VERSION 5.7 ;
  NOWIREEXTENSIONATPIN ON ;
  DIVIDERCHAR "/" ;
  BUSBITCHARS "[]" ;
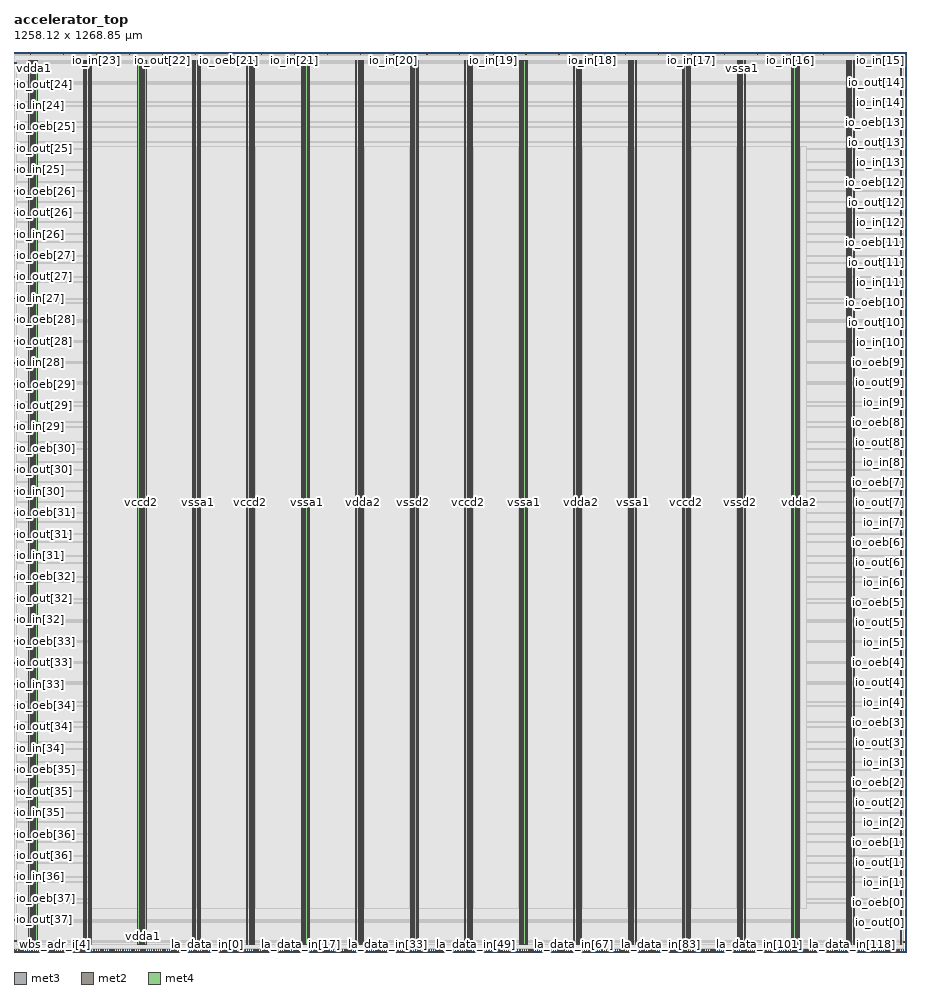
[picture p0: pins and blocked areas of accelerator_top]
MACRO accelerator_top
  CLASS BLOCK ;
  FOREIGN accelerator_top ;
  ORIGIN 0.000 0.000 ;
  SIZE 1258.125 BY 1268.845 ;
  PIN io_in[0]
    DIRECTION INPUT ;
    USE SIGNAL ;
    PORT
      LAYER met3 ;
        RECT 1254.125 13.640 1258.125 14.240 ;
    END
  END io_in[0]
  PIN io_in[10]
    DIRECTION INPUT ;
    USE SIGNAL ;
    PORT
      LAYER met3 ;
        RECT 1254.125 859.560 1258.125 860.160 ;
    END
  END io_in[10]
  PIN io_in[11]
    DIRECTION INPUT ;
    USE SIGNAL ;
    PORT
      LAYER met3 ;
        RECT 1254.125 943.880 1258.125 944.480 ;
    END
  END io_in[11]
  PIN io_in[12]
    DIRECTION INPUT ;
    USE SIGNAL ;
    PORT
      LAYER met3 ;
        RECT 1254.125 1028.200 1258.125 1028.800 ;
    END
  END io_in[12]
  PIN io_in[13]
    DIRECTION INPUT ;
    USE SIGNAL ;
    PORT
      LAYER met3 ;
        RECT 1254.125 1113.200 1258.125 1113.800 ;
    END
  END io_in[13]
  PIN io_in[14]
    DIRECTION INPUT ;
    USE SIGNAL ;
    PORT
      LAYER met3 ;
        RECT 1254.125 1197.520 1258.125 1198.120 ;
    END
  END io_in[14]
  PIN io_in[15]
    DIRECTION INPUT ;
    USE SIGNAL ;
    PORT
      LAYER met2 ;
        RECT 1234.270 1264.845 1234.550 1268.845 ;
    END
  END io_in[15]
  PIN io_in[16]
    DIRECTION INPUT ;
    USE SIGNAL ;
    PORT
      LAYER met2 ;
        RECT 1094.430 1264.845 1094.710 1268.845 ;
    END
  END io_in[16]
  PIN io_in[17]
    DIRECTION INPUT ;
    USE SIGNAL ;
    PORT
      LAYER met2 ;
        RECT 954.590 1264.845 954.870 1268.845 ;
    END
  END io_in[17]
  PIN io_in[18]
    DIRECTION INPUT ;
    USE SIGNAL ;
    PORT
      LAYER met2 ;
        RECT 815.210 1264.845 815.490 1268.845 ;
    END
  END io_in[18]
  PIN io_in[19]
    DIRECTION INPUT ;
    USE SIGNAL ;
    PORT
      LAYER met2 ;
        RECT 675.370 1264.845 675.650 1268.845 ;
    END
  END io_in[19]
  PIN io_in[1]
    DIRECTION INPUT ;
    USE SIGNAL ;
    PORT
      LAYER met3 ;
        RECT 1254.125 97.960 1258.125 98.560 ;
    END
  END io_in[1]
  PIN io_in[20]
    DIRECTION INPUT ;
    USE SIGNAL ;
    PORT
      LAYER met2 ;
        RECT 535.530 1264.845 535.810 1268.845 ;
    END
  END io_in[20]
  PIN io_in[21]
    DIRECTION INPUT ;
    USE SIGNAL ;
    PORT
      LAYER met2 ;
        RECT 395.690 1264.845 395.970 1268.845 ;
    END
  END io_in[21]
  PIN io_in[22]
    DIRECTION INPUT ;
    USE SIGNAL ;
    PORT
      LAYER met2 ;
        RECT 255.850 1264.845 256.130 1268.845 ;
    END
  END io_in[22]
  PIN io_in[23]
    DIRECTION INPUT ;
    USE SIGNAL ;
    PORT
      LAYER met2 ;
        RECT 116.010 1264.845 116.290 1268.845 ;
    END
  END io_in[23]
  PIN io_in[24]
    DIRECTION INPUT ;
    USE SIGNAL ;
    PORT
      LAYER met3 ;
        RECT 0.000 1192.760 4.000 1193.360 ;
    END
  END io_in[24]
  PIN io_in[25]
    DIRECTION INPUT ;
    USE SIGNAL ;
    PORT
      LAYER met3 ;
        RECT 0.000 1102.320 4.000 1102.920 ;
    END
  END io_in[25]
  PIN io_in[26]
    DIRECTION INPUT ;
    USE SIGNAL ;
    PORT
      LAYER met3 ;
        RECT 0.000 1011.880 4.000 1012.480 ;
    END
  END io_in[26]
  PIN io_in[27]
    DIRECTION INPUT ;
    USE SIGNAL ;
    PORT
      LAYER met3 ;
        RECT 0.000 920.760 4.000 921.360 ;
    END
  END io_in[27]
  PIN io_in[28]
    DIRECTION INPUT ;
    USE SIGNAL ;
    PORT
      LAYER met3 ;
        RECT 0.000 830.320 4.000 830.920 ;
    END
  END io_in[28]
  PIN io_in[29]
    DIRECTION INPUT ;
    USE SIGNAL ;
    PORT
      LAYER met3 ;
        RECT 0.000 739.880 4.000 740.480 ;
    END
  END io_in[29]
  PIN io_in[2]
    DIRECTION INPUT ;
    USE SIGNAL ;
    PORT
      LAYER met3 ;
        RECT 1254.125 182.280 1258.125 182.880 ;
    END
  END io_in[2]
  PIN io_in[30]
    DIRECTION INPUT ;
    USE SIGNAL ;
    PORT
      LAYER met3 ;
        RECT 0.000 649.440 4.000 650.040 ;
    END
  END io_in[30]
  PIN io_in[31]
    DIRECTION INPUT ;
    USE SIGNAL ;
    PORT
      LAYER met3 ;
        RECT 0.000 558.320 4.000 558.920 ;
    END
  END io_in[31]
  PIN io_in[32]
    DIRECTION INPUT ;
    USE SIGNAL ;
    PORT
      LAYER met3 ;
        RECT 0.000 467.880 4.000 468.480 ;
    END
  END io_in[32]
  PIN io_in[33]
    DIRECTION INPUT ;
    USE SIGNAL ;
    PORT
      LAYER met3 ;
        RECT 0.000 377.440 4.000 378.040 ;
    END
  END io_in[33]
  PIN io_in[34]
    DIRECTION INPUT ;
    USE SIGNAL ;
    PORT
      LAYER met3 ;
        RECT 0.000 286.320 4.000 286.920 ;
    END
  END io_in[34]
  PIN io_in[35]
    DIRECTION INPUT ;
    USE SIGNAL ;
    PORT
      LAYER met3 ;
        RECT 0.000 195.880 4.000 196.480 ;
    END
  END io_in[35]
  PIN io_in[36]
    DIRECTION INPUT ;
    USE SIGNAL ;
    PORT
      LAYER met3 ;
        RECT 0.000 105.440 4.000 106.040 ;
    END
  END io_in[36]
  PIN io_in[37]
    DIRECTION INPUT ;
    USE SIGNAL ;
    PORT
      LAYER met3 ;
        RECT 0.000 15.000 4.000 15.600 ;
    END
  END io_in[37]
  PIN io_in[3]
    DIRECTION INPUT ;
    USE SIGNAL ;
    PORT
      LAYER met3 ;
        RECT 1254.125 267.280 1258.125 267.880 ;
    END
  END io_in[3]
  PIN io_in[4]
    DIRECTION INPUT ;
    USE SIGNAL ;
    PORT
      LAYER met3 ;
        RECT 1254.125 351.600 1258.125 352.200 ;
    END
  END io_in[4]
  PIN io_in[5]
    DIRECTION INPUT ;
    USE SIGNAL ;
    PORT
      LAYER met3 ;
        RECT 1254.125 436.600 1258.125 437.200 ;
    END
  END io_in[5]
  PIN io_in[6]
    DIRECTION INPUT ;
    USE SIGNAL ;
    PORT
      LAYER met3 ;
        RECT 1254.125 520.920 1258.125 521.520 ;
    END
  END io_in[6]
  PIN io_in[7]
    DIRECTION INPUT ;
    USE SIGNAL ;
    PORT
      LAYER met3 ;
        RECT 1254.125 605.240 1258.125 605.840 ;
    END
  END io_in[7]
  PIN io_in[8]
    DIRECTION INPUT ;
    USE SIGNAL ;
    PORT
      LAYER met3 ;
        RECT 1254.125 690.240 1258.125 690.840 ;
    END
  END io_in[8]
  PIN io_in[9]
    DIRECTION INPUT ;
    USE SIGNAL ;
    PORT
      LAYER met3 ;
        RECT 1254.125 774.560 1258.125 775.160 ;
    END
  END io_in[9]
  PIN io_oeb[0]
    DIRECTION OUTPUT TRISTATE ;
    USE SIGNAL ;
    PORT
      LAYER met3 ;
        RECT 1254.125 69.400 1258.125 70.000 ;
    END
  END io_oeb[0]
  PIN io_oeb[10]
    DIRECTION OUTPUT TRISTATE ;
    USE SIGNAL ;
    PORT
      LAYER met3 ;
        RECT 1254.125 915.320 1258.125 915.920 ;
    END
  END io_oeb[10]
  PIN io_oeb[11]
    DIRECTION OUTPUT TRISTATE ;
    USE SIGNAL ;
    PORT
      LAYER met3 ;
        RECT 1254.125 1000.320 1258.125 1000.920 ;
    END
  END io_oeb[11]
  PIN io_oeb[12]
    DIRECTION OUTPUT TRISTATE ;
    USE SIGNAL ;
    PORT
      LAYER met3 ;
        RECT 1254.125 1084.640 1258.125 1085.240 ;
    END
  END io_oeb[12]
  PIN io_oeb[13]
    DIRECTION OUTPUT TRISTATE ;
    USE SIGNAL ;
    PORT
      LAYER met3 ;
        RECT 1254.125 1169.640 1258.125 1170.240 ;
    END
  END io_oeb[13]
  PIN io_oeb[14]
    DIRECTION OUTPUT TRISTATE ;
    USE SIGNAL ;
    PORT
      LAYER met3 ;
        RECT 1254.125 1253.960 1258.125 1254.560 ;
    END
  END io_oeb[14]
  PIN io_oeb[15]
    DIRECTION OUTPUT TRISTATE ;
    USE SIGNAL ;
    PORT
      LAYER met2 ;
        RECT 1141.350 1264.845 1141.630 1268.845 ;
    END
  END io_oeb[15]
  PIN io_oeb[16]
    DIRECTION OUTPUT TRISTATE ;
    USE SIGNAL ;
    PORT
      LAYER met2 ;
        RECT 1001.510 1264.845 1001.790 1268.845 ;
    END
  END io_oeb[16]
  PIN io_oeb[17]
    DIRECTION OUTPUT TRISTATE ;
    USE SIGNAL ;
    PORT
      LAYER met2 ;
        RECT 861.670 1264.845 861.950 1268.845 ;
    END
  END io_oeb[17]
  PIN io_oeb[18]
    DIRECTION OUTPUT TRISTATE ;
    USE SIGNAL ;
    PORT
      LAYER met2 ;
        RECT 721.830 1264.845 722.110 1268.845 ;
    END
  END io_oeb[18]
  PIN io_oeb[19]
    DIRECTION OUTPUT TRISTATE ;
    USE SIGNAL ;
    PORT
      LAYER met2 ;
        RECT 581.990 1264.845 582.270 1268.845 ;
    END
  END io_oeb[19]
  PIN io_oeb[1]
    DIRECTION OUTPUT TRISTATE ;
    USE SIGNAL ;
    PORT
      LAYER met3 ;
        RECT 1254.125 154.400 1258.125 155.000 ;
    END
  END io_oeb[1]
  PIN io_oeb[20]
    DIRECTION OUTPUT TRISTATE ;
    USE SIGNAL ;
    PORT
      LAYER met2 ;
        RECT 442.150 1264.845 442.430 1268.845 ;
    END
  END io_oeb[20]
  PIN io_oeb[21]
    DIRECTION OUTPUT TRISTATE ;
    USE SIGNAL ;
    PORT
      LAYER met2 ;
        RECT 302.310 1264.845 302.590 1268.845 ;
    END
  END io_oeb[21]
  PIN io_oeb[22]
    DIRECTION OUTPUT TRISTATE ;
    USE SIGNAL ;
    PORT
      LAYER met2 ;
        RECT 162.470 1264.845 162.750 1268.845 ;
    END
  END io_oeb[22]
  PIN io_oeb[23]
    DIRECTION OUTPUT TRISTATE ;
    USE SIGNAL ;
    PORT
      LAYER met2 ;
        RECT 23.090 1264.845 23.370 1268.845 ;
    END
  END io_oeb[23]
  PIN io_oeb[24]
    DIRECTION OUTPUT TRISTATE ;
    USE SIGNAL ;
    PORT
      LAYER met3 ;
        RECT 0.000 1253.280 4.000 1253.880 ;
    END
  END io_oeb[24]
  PIN io_oeb[25]
    DIRECTION OUTPUT TRISTATE ;
    USE SIGNAL ;
    PORT
      LAYER met3 ;
        RECT 0.000 1162.840 4.000 1163.440 ;
    END
  END io_oeb[25]
  PIN io_oeb[26]
    DIRECTION OUTPUT TRISTATE ;
    USE SIGNAL ;
    PORT
      LAYER met3 ;
        RECT 0.000 1072.400 4.000 1073.000 ;
    END
  END io_oeb[26]
  PIN io_oeb[27]
    DIRECTION OUTPUT TRISTATE ;
    USE SIGNAL ;
    PORT
      LAYER met3 ;
        RECT 0.000 981.280 4.000 981.880 ;
    END
  END io_oeb[27]
  PIN io_oeb[28]
    DIRECTION OUTPUT TRISTATE ;
    USE SIGNAL ;
    PORT
      LAYER met3 ;
        RECT 0.000 890.840 4.000 891.440 ;
    END
  END io_oeb[28]
  PIN io_oeb[29]
    DIRECTION OUTPUT TRISTATE ;
    USE SIGNAL ;
    PORT
      LAYER met3 ;
        RECT 0.000 800.400 4.000 801.000 ;
    END
  END io_oeb[29]
  PIN io_oeb[2]
    DIRECTION OUTPUT TRISTATE ;
    USE SIGNAL ;
    PORT
      LAYER met3 ;
        RECT 1254.125 238.720 1258.125 239.320 ;
    END
  END io_oeb[2]
  PIN io_oeb[30]
    DIRECTION OUTPUT TRISTATE ;
    USE SIGNAL ;
    PORT
      LAYER met3 ;
        RECT 0.000 709.280 4.000 709.880 ;
    END
  END io_oeb[30]
  PIN io_oeb[31]
    DIRECTION OUTPUT TRISTATE ;
    USE SIGNAL ;
    PORT
      LAYER met3 ;
        RECT 0.000 618.840 4.000 619.440 ;
    END
  END io_oeb[31]
  PIN io_oeb[32]
    DIRECTION OUTPUT TRISTATE ;
    USE SIGNAL ;
    PORT
      LAYER met3 ;
        RECT 0.000 528.400 4.000 529.000 ;
    END
  END io_oeb[32]
  PIN io_oeb[33]
    DIRECTION OUTPUT TRISTATE ;
    USE SIGNAL ;
    PORT
      LAYER met3 ;
        RECT 0.000 437.960 4.000 438.560 ;
    END
  END io_oeb[33]
  PIN io_oeb[34]
    DIRECTION OUTPUT TRISTATE ;
    USE SIGNAL ;
    PORT
      LAYER met3 ;
        RECT 0.000 346.840 4.000 347.440 ;
    END
  END io_oeb[34]
  PIN io_oeb[35]
    DIRECTION OUTPUT TRISTATE ;
    USE SIGNAL ;
    PORT
      LAYER met3 ;
        RECT 0.000 256.400 4.000 257.000 ;
    END
  END io_oeb[35]
  PIN io_oeb[36]
    DIRECTION OUTPUT TRISTATE ;
    USE SIGNAL ;
    PORT
      LAYER met3 ;
        RECT 0.000 165.960 4.000 166.560 ;
    END
  END io_oeb[36]
  PIN io_oeb[37]
    DIRECTION OUTPUT TRISTATE ;
    USE SIGNAL ;
    PORT
      LAYER met3 ;
        RECT 0.000 74.840 4.000 75.440 ;
    END
  END io_oeb[37]
  PIN io_oeb[3]
    DIRECTION OUTPUT TRISTATE ;
    USE SIGNAL ;
    PORT
      LAYER met3 ;
        RECT 1254.125 323.720 1258.125 324.320 ;
    END
  END io_oeb[3]
  PIN io_oeb[4]
    DIRECTION OUTPUT TRISTATE ;
    USE SIGNAL ;
    PORT
      LAYER met3 ;
        RECT 1254.125 408.040 1258.125 408.640 ;
    END
  END io_oeb[4]
  PIN io_oeb[5]
    DIRECTION OUTPUT TRISTATE ;
    USE SIGNAL ;
    PORT
      LAYER met3 ;
        RECT 1254.125 492.360 1258.125 492.960 ;
    END
  END io_oeb[5]
  PIN io_oeb[6]
    DIRECTION OUTPUT TRISTATE ;
    USE SIGNAL ;
    PORT
      LAYER met3 ;
        RECT 1254.125 577.360 1258.125 577.960 ;
    END
  END io_oeb[6]
  PIN io_oeb[7]
    DIRECTION OUTPUT TRISTATE ;
    USE SIGNAL ;
    PORT
      LAYER met3 ;
        RECT 1254.125 661.680 1258.125 662.280 ;
    END
  END io_oeb[7]
  PIN io_oeb[8]
    DIRECTION OUTPUT TRISTATE ;
    USE SIGNAL ;
    PORT
      LAYER met3 ;
        RECT 1254.125 746.680 1258.125 747.280 ;
    END
  END io_oeb[8]
  PIN io_oeb[9]
    DIRECTION OUTPUT TRISTATE ;
    USE SIGNAL ;
    PORT
      LAYER met3 ;
        RECT 1254.125 831.000 1258.125 831.600 ;
    END
  END io_oeb[9]
  PIN io_out[0]
    DIRECTION OUTPUT TRISTATE ;
    USE SIGNAL ;
    PORT
      LAYER met3 ;
        RECT 1254.125 41.520 1258.125 42.120 ;
    END
  END io_out[0]
  PIN io_out[10]
    DIRECTION OUTPUT TRISTATE ;
    USE SIGNAL ;
    PORT
      LAYER met3 ;
        RECT 1254.125 887.440 1258.125 888.040 ;
    END
  END io_out[10]
  PIN io_out[11]
    DIRECTION OUTPUT TRISTATE ;
    USE SIGNAL ;
    PORT
      LAYER met3 ;
        RECT 1254.125 971.760 1258.125 972.360 ;
    END
  END io_out[11]
  PIN io_out[12]
    DIRECTION OUTPUT TRISTATE ;
    USE SIGNAL ;
    PORT
      LAYER met3 ;
        RECT 1254.125 1056.760 1258.125 1057.360 ;
    END
  END io_out[12]
  PIN io_out[13]
    DIRECTION OUTPUT TRISTATE ;
    USE SIGNAL ;
    PORT
      LAYER met3 ;
        RECT 1254.125 1141.080 1258.125 1141.680 ;
    END
  END io_out[13]
  PIN io_out[14]
    DIRECTION OUTPUT TRISTATE ;
    USE SIGNAL ;
    PORT
      LAYER met3 ;
        RECT 1254.125 1226.080 1258.125 1226.680 ;
    END
  END io_out[14]
  PIN io_out[15]
    DIRECTION OUTPUT TRISTATE ;
    USE SIGNAL ;
    PORT
      LAYER met2 ;
        RECT 1187.810 1264.845 1188.090 1268.845 ;
    END
  END io_out[15]
  PIN io_out[16]
    DIRECTION OUTPUT TRISTATE ;
    USE SIGNAL ;
    PORT
      LAYER met2 ;
        RECT 1047.970 1264.845 1048.250 1268.845 ;
    END
  END io_out[16]
  PIN io_out[17]
    DIRECTION OUTPUT TRISTATE ;
    USE SIGNAL ;
    PORT
      LAYER met2 ;
        RECT 908.130 1264.845 908.410 1268.845 ;
    END
  END io_out[17]
  PIN io_out[18]
    DIRECTION OUTPUT TRISTATE ;
    USE SIGNAL ;
    PORT
      LAYER met2 ;
        RECT 768.290 1264.845 768.570 1268.845 ;
    END
  END io_out[18]
  PIN io_out[19]
    DIRECTION OUTPUT TRISTATE ;
    USE SIGNAL ;
    PORT
      LAYER met2 ;
        RECT 628.450 1264.845 628.730 1268.845 ;
    END
  END io_out[19]
  PIN io_out[1]
    DIRECTION OUTPUT TRISTATE ;
    USE SIGNAL ;
    PORT
      LAYER met3 ;
        RECT 1254.125 125.840 1258.125 126.440 ;
    END
  END io_out[1]
  PIN io_out[20]
    DIRECTION OUTPUT TRISTATE ;
    USE SIGNAL ;
    PORT
      LAYER met2 ;
        RECT 488.610 1264.845 488.890 1268.845 ;
    END
  END io_out[20]
  PIN io_out[21]
    DIRECTION OUTPUT TRISTATE ;
    USE SIGNAL ;
    PORT
      LAYER met2 ;
        RECT 349.230 1264.845 349.510 1268.845 ;
    END
  END io_out[21]
  PIN io_out[22]
    DIRECTION OUTPUT TRISTATE ;
    USE SIGNAL ;
    PORT
      LAYER met2 ;
        RECT 209.390 1264.845 209.670 1268.845 ;
    END
  END io_out[22]
  PIN io_out[23]
    DIRECTION OUTPUT TRISTATE ;
    USE SIGNAL ;
    PORT
      LAYER met2 ;
        RECT 69.550 1264.845 69.830 1268.845 ;
    END
  END io_out[23]
  PIN io_out[24]
    DIRECTION OUTPUT TRISTATE ;
    USE SIGNAL ;
    PORT
      LAYER met3 ;
        RECT 0.000 1223.360 4.000 1223.960 ;
    END
  END io_out[24]
  PIN io_out[25]
    DIRECTION OUTPUT TRISTATE ;
    USE SIGNAL ;
    PORT
      LAYER met3 ;
        RECT 0.000 1132.240 4.000 1132.840 ;
    END
  END io_out[25]
  PIN io_out[26]
    DIRECTION OUTPUT TRISTATE ;
    USE SIGNAL ;
    PORT
      LAYER met3 ;
        RECT 0.000 1041.800 4.000 1042.400 ;
    END
  END io_out[26]
  PIN io_out[27]
    DIRECTION OUTPUT TRISTATE ;
    USE SIGNAL ;
    PORT
      LAYER met3 ;
        RECT 0.000 951.360 4.000 951.960 ;
    END
  END io_out[27]
  PIN io_out[28]
    DIRECTION OUTPUT TRISTATE ;
    USE SIGNAL ;
    PORT
      LAYER met3 ;
        RECT 0.000 860.920 4.000 861.520 ;
    END
  END io_out[28]
  PIN io_out[29]
    DIRECTION OUTPUT TRISTATE ;
    USE SIGNAL ;
    PORT
      LAYER met3 ;
        RECT 0.000 769.800 4.000 770.400 ;
    END
  END io_out[29]
  PIN io_out[2]
    DIRECTION OUTPUT TRISTATE ;
    USE SIGNAL ;
    PORT
      LAYER met3 ;
        RECT 1254.125 210.840 1258.125 211.440 ;
    END
  END io_out[2]
  PIN io_out[30]
    DIRECTION OUTPUT TRISTATE ;
    USE SIGNAL ;
    PORT
      LAYER met3 ;
        RECT 0.000 679.360 4.000 679.960 ;
    END
  END io_out[30]
  PIN io_out[31]
    DIRECTION OUTPUT TRISTATE ;
    USE SIGNAL ;
    PORT
      LAYER met3 ;
        RECT 0.000 588.920 4.000 589.520 ;
    END
  END io_out[31]
  PIN io_out[32]
    DIRECTION OUTPUT TRISTATE ;
    USE SIGNAL ;
    PORT
      LAYER met3 ;
        RECT 0.000 497.800 4.000 498.400 ;
    END
  END io_out[32]
  PIN io_out[33]
    DIRECTION OUTPUT TRISTATE ;
    USE SIGNAL ;
    PORT
      LAYER met3 ;
        RECT 0.000 407.360 4.000 407.960 ;
    END
  END io_out[33]
  PIN io_out[34]
    DIRECTION OUTPUT TRISTATE ;
    USE SIGNAL ;
    PORT
      LAYER met3 ;
        RECT 0.000 316.920 4.000 317.520 ;
    END
  END io_out[34]
  PIN io_out[35]
    DIRECTION OUTPUT TRISTATE ;
    USE SIGNAL ;
    PORT
      LAYER met3 ;
        RECT 0.000 226.480 4.000 227.080 ;
    END
  END io_out[35]
  PIN io_out[36]
    DIRECTION OUTPUT TRISTATE ;
    USE SIGNAL ;
    PORT
      LAYER met3 ;
        RECT 0.000 135.360 4.000 135.960 ;
    END
  END io_out[36]
  PIN io_out[37]
    DIRECTION OUTPUT TRISTATE ;
    USE SIGNAL ;
    PORT
      LAYER met3 ;
        RECT 0.000 44.920 4.000 45.520 ;
    END
  END io_out[37]
  PIN io_out[3]
    DIRECTION OUTPUT TRISTATE ;
    USE SIGNAL ;
    PORT
      LAYER met3 ;
        RECT 1254.125 295.160 1258.125 295.760 ;
    END
  END io_out[3]
  PIN io_out[4]
    DIRECTION OUTPUT TRISTATE ;
    USE SIGNAL ;
    PORT
      LAYER met3 ;
        RECT 1254.125 380.160 1258.125 380.760 ;
    END
  END io_out[4]
  PIN io_out[5]
    DIRECTION OUTPUT TRISTATE ;
    USE SIGNAL ;
    PORT
      LAYER met3 ;
        RECT 1254.125 464.480 1258.125 465.080 ;
    END
  END io_out[5]
  PIN io_out[6]
    DIRECTION OUTPUT TRISTATE ;
    USE SIGNAL ;
    PORT
      LAYER met3 ;
        RECT 1254.125 548.800 1258.125 549.400 ;
    END
  END io_out[6]
  PIN io_out[7]
    DIRECTION OUTPUT TRISTATE ;
    USE SIGNAL ;
    PORT
      LAYER met3 ;
        RECT 1254.125 633.800 1258.125 634.400 ;
    END
  END io_out[7]
  PIN io_out[8]
    DIRECTION OUTPUT TRISTATE ;
    USE SIGNAL ;
    PORT
      LAYER met3 ;
        RECT 1254.125 718.120 1258.125 718.720 ;
    END
  END io_out[8]
  PIN io_out[9]
    DIRECTION OUTPUT TRISTATE ;
    USE SIGNAL ;
    PORT
      LAYER met3 ;
        RECT 1254.125 803.120 1258.125 803.720 ;
    END
  END io_out[9]
  PIN la_data_in[0]
    DIRECTION INPUT ;
    USE SIGNAL ;
    PORT
      LAYER met2 ;
        RECT 272.870 0.000 273.150 4.000 ;
    END
  END la_data_in[0]
  PIN la_data_in[100]
    DIRECTION INPUT ;
    USE SIGNAL ;
    PORT
      LAYER met2 ;
        RECT 1043.370 0.000 1043.650 4.000 ;
    END
  END la_data_in[100]
  PIN la_data_in[101]
    DIRECTION INPUT ;
    USE SIGNAL ;
    PORT
      LAYER met2 ;
        RECT 1050.730 0.000 1051.010 4.000 ;
    END
  END la_data_in[101]
  PIN la_data_in[102]
    DIRECTION INPUT ;
    USE SIGNAL ;
    PORT
      LAYER met2 ;
        RECT 1058.550 0.000 1058.830 4.000 ;
    END
  END la_data_in[102]
  PIN la_data_in[103]
    DIRECTION INPUT ;
    USE SIGNAL ;
    PORT
      LAYER met2 ;
        RECT 1066.370 0.000 1066.650 4.000 ;
    END
  END la_data_in[103]
  PIN la_data_in[104]
    DIRECTION INPUT ;
    USE SIGNAL ;
    PORT
      LAYER met2 ;
        RECT 1074.190 0.000 1074.470 4.000 ;
    END
  END la_data_in[104]
  PIN la_data_in[105]
    DIRECTION INPUT ;
    USE SIGNAL ;
    PORT
      LAYER met2 ;
        RECT 1081.550 0.000 1081.830 4.000 ;
    END
  END la_data_in[105]
  PIN la_data_in[106]
    DIRECTION INPUT ;
    USE SIGNAL ;
    PORT
      LAYER met2 ;
        RECT 1089.370 0.000 1089.650 4.000 ;
    END
  END la_data_in[106]
  PIN la_data_in[107]
    DIRECTION INPUT ;
    USE SIGNAL ;
    PORT
      LAYER met2 ;
        RECT 1097.190 0.000 1097.470 4.000 ;
    END
  END la_data_in[107]
  PIN la_data_in[108]
    DIRECTION INPUT ;
    USE SIGNAL ;
    PORT
      LAYER met2 ;
        RECT 1105.010 0.000 1105.290 4.000 ;
    END
  END la_data_in[108]
  PIN la_data_in[109]
    DIRECTION INPUT ;
    USE SIGNAL ;
    PORT
      LAYER met2 ;
        RECT 1112.370 0.000 1112.650 4.000 ;
    END
  END la_data_in[109]
  PIN la_data_in[10]
    DIRECTION INPUT ;
    USE SIGNAL ;
    PORT
      LAYER met2 ;
        RECT 350.150 0.000 350.430 4.000 ;
    END
  END la_data_in[10]
  PIN la_data_in[110]
    DIRECTION INPUT ;
    USE SIGNAL ;
    PORT
      LAYER met2 ;
        RECT 1120.190 0.000 1120.470 4.000 ;
    END
  END la_data_in[110]
  PIN la_data_in[111]
    DIRECTION INPUT ;
    USE SIGNAL ;
    PORT
      LAYER met2 ;
        RECT 1128.010 0.000 1128.290 4.000 ;
    END
  END la_data_in[111]
  PIN la_data_in[112]
    DIRECTION INPUT ;
    USE SIGNAL ;
    PORT
      LAYER met2 ;
        RECT 1135.830 0.000 1136.110 4.000 ;
    END
  END la_data_in[112]
  PIN la_data_in[113]
    DIRECTION INPUT ;
    USE SIGNAL ;
    PORT
      LAYER met2 ;
        RECT 1143.190 0.000 1143.470 4.000 ;
    END
  END la_data_in[113]
  PIN la_data_in[114]
    DIRECTION INPUT ;
    USE SIGNAL ;
    PORT
      LAYER met2 ;
        RECT 1151.010 0.000 1151.290 4.000 ;
    END
  END la_data_in[114]
  PIN la_data_in[115]
    DIRECTION INPUT ;
    USE SIGNAL ;
    PORT
      LAYER met2 ;
        RECT 1158.830 0.000 1159.110 4.000 ;
    END
  END la_data_in[115]
  PIN la_data_in[116]
    DIRECTION INPUT ;
    USE SIGNAL ;
    PORT
      LAYER met2 ;
        RECT 1166.650 0.000 1166.930 4.000 ;
    END
  END la_data_in[116]
  PIN la_data_in[117]
    DIRECTION INPUT ;
    USE SIGNAL ;
    PORT
      LAYER met2 ;
        RECT 1174.010 0.000 1174.290 4.000 ;
    END
  END la_data_in[117]
  PIN la_data_in[118]
    DIRECTION INPUT ;
    USE SIGNAL ;
    PORT
      LAYER met2 ;
        RECT 1181.830 0.000 1182.110 4.000 ;
    END
  END la_data_in[118]
  PIN la_data_in[119]
    DIRECTION INPUT ;
    USE SIGNAL ;
    PORT
      LAYER met2 ;
        RECT 1189.650 0.000 1189.930 4.000 ;
    END
  END la_data_in[119]
  PIN la_data_in[11]
    DIRECTION INPUT ;
    USE SIGNAL ;
    PORT
      LAYER met2 ;
        RECT 357.510 0.000 357.790 4.000 ;
    END
  END la_data_in[11]
  PIN la_data_in[120]
    DIRECTION INPUT ;
    USE SIGNAL ;
    PORT
      LAYER met2 ;
        RECT 1197.470 0.000 1197.750 4.000 ;
    END
  END la_data_in[120]
  PIN la_data_in[121]
    DIRECTION INPUT ;
    USE SIGNAL ;
    PORT
      LAYER met2 ;
        RECT 1204.830 0.000 1205.110 4.000 ;
    END
  END la_data_in[121]
  PIN la_data_in[122]
    DIRECTION INPUT ;
    USE SIGNAL ;
    PORT
      LAYER met2 ;
        RECT 1212.650 0.000 1212.930 4.000 ;
    END
  END la_data_in[122]
  PIN la_data_in[123]
    DIRECTION INPUT ;
    USE SIGNAL ;
    PORT
      LAYER met2 ;
        RECT 1220.470 0.000 1220.750 4.000 ;
    END
  END la_data_in[123]
  PIN la_data_in[124]
    DIRECTION INPUT ;
    USE SIGNAL ;
    PORT
      LAYER met2 ;
        RECT 1228.290 0.000 1228.570 4.000 ;
    END
  END la_data_in[124]
  PIN la_data_in[125]
    DIRECTION INPUT ;
    USE SIGNAL ;
    PORT
      LAYER met2 ;
        RECT 1235.650 0.000 1235.930 4.000 ;
    END
  END la_data_in[125]
  PIN la_data_in[126]
    DIRECTION INPUT ;
    USE SIGNAL ;
    PORT
      LAYER met2 ;
        RECT 1243.470 0.000 1243.750 4.000 ;
    END
  END la_data_in[126]
  PIN la_data_in[127]
    DIRECTION INPUT ;
    USE SIGNAL ;
    PORT
      LAYER met2 ;
        RECT 1251.290 0.000 1251.570 4.000 ;
    END
  END la_data_in[127]
  PIN la_data_in[12]
    DIRECTION INPUT ;
    USE SIGNAL ;
    PORT
      LAYER met2 ;
        RECT 365.330 0.000 365.610 4.000 ;
    END
  END la_data_in[12]
  PIN la_data_in[13]
    DIRECTION INPUT ;
    USE SIGNAL ;
    PORT
      LAYER met2 ;
        RECT 373.150 0.000 373.430 4.000 ;
    END
  END la_data_in[13]
  PIN la_data_in[14]
    DIRECTION INPUT ;
    USE SIGNAL ;
    PORT
      LAYER met2 ;
        RECT 380.970 0.000 381.250 4.000 ;
    END
  END la_data_in[14]
  PIN la_data_in[15]
    DIRECTION INPUT ;
    USE SIGNAL ;
    PORT
      LAYER met2 ;
        RECT 388.330 0.000 388.610 4.000 ;
    END
  END la_data_in[15]
  PIN la_data_in[16]
    DIRECTION INPUT ;
    USE SIGNAL ;
    PORT
      LAYER met2 ;
        RECT 396.150 0.000 396.430 4.000 ;
    END
  END la_data_in[16]
  PIN la_data_in[17]
    DIRECTION INPUT ;
    USE SIGNAL ;
    PORT
      LAYER met2 ;
        RECT 403.970 0.000 404.250 4.000 ;
    END
  END la_data_in[17]
  PIN la_data_in[18]
    DIRECTION INPUT ;
    USE SIGNAL ;
    PORT
      LAYER met2 ;
        RECT 411.790 0.000 412.070 4.000 ;
    END
  END la_data_in[18]
  PIN la_data_in[19]
    DIRECTION INPUT ;
    USE SIGNAL ;
    PORT
      LAYER met2 ;
        RECT 419.150 0.000 419.430 4.000 ;
    END
  END la_data_in[19]
  PIN la_data_in[1]
    DIRECTION INPUT ;
    USE SIGNAL ;
    PORT
      LAYER met2 ;
        RECT 280.690 0.000 280.970 4.000 ;
    END
  END la_data_in[1]
  PIN la_data_in[20]
    DIRECTION INPUT ;
    USE SIGNAL ;
    PORT
      LAYER met2 ;
        RECT 426.970 0.000 427.250 4.000 ;
    END
  END la_data_in[20]
  PIN la_data_in[21]
    DIRECTION INPUT ;
    USE SIGNAL ;
    PORT
      LAYER met2 ;
        RECT 434.790 0.000 435.070 4.000 ;
    END
  END la_data_in[21]
  PIN la_data_in[22]
    DIRECTION INPUT ;
    USE SIGNAL ;
    PORT
      LAYER met2 ;
        RECT 442.610 0.000 442.890 4.000 ;
    END
  END la_data_in[22]
  PIN la_data_in[23]
    DIRECTION INPUT ;
    USE SIGNAL ;
    PORT
      LAYER met2 ;
        RECT 449.970 0.000 450.250 4.000 ;
    END
  END la_data_in[23]
  PIN la_data_in[24]
    DIRECTION INPUT ;
    USE SIGNAL ;
    PORT
      LAYER met2 ;
        RECT 457.790 0.000 458.070 4.000 ;
    END
  END la_data_in[24]
  PIN la_data_in[25]
    DIRECTION INPUT ;
    USE SIGNAL ;
    PORT
      LAYER met2 ;
        RECT 465.610 0.000 465.890 4.000 ;
    END
  END la_data_in[25]
  PIN la_data_in[26]
    DIRECTION INPUT ;
    USE SIGNAL ;
    PORT
      LAYER met2 ;
        RECT 473.430 0.000 473.710 4.000 ;
    END
  END la_data_in[26]
  PIN la_data_in[27]
    DIRECTION INPUT ;
    USE SIGNAL ;
    PORT
      LAYER met2 ;
        RECT 480.790 0.000 481.070 4.000 ;
    END
  END la_data_in[27]
  PIN la_data_in[28]
    DIRECTION INPUT ;
    USE SIGNAL ;
    PORT
      LAYER met2 ;
        RECT 488.610 0.000 488.890 4.000 ;
    END
  END la_data_in[28]
  PIN la_data_in[29]
    DIRECTION INPUT ;
    USE SIGNAL ;
    PORT
      LAYER met2 ;
        RECT 496.430 0.000 496.710 4.000 ;
    END
  END la_data_in[29]
  PIN la_data_in[2]
    DIRECTION INPUT ;
    USE SIGNAL ;
    PORT
      LAYER met2 ;
        RECT 288.510 0.000 288.790 4.000 ;
    END
  END la_data_in[2]
  PIN la_data_in[30]
    DIRECTION INPUT ;
    USE SIGNAL ;
    PORT
      LAYER met2 ;
        RECT 504.250 0.000 504.530 4.000 ;
    END
  END la_data_in[30]
  PIN la_data_in[31]
    DIRECTION INPUT ;
    USE SIGNAL ;
    PORT
      LAYER met2 ;
        RECT 511.610 0.000 511.890 4.000 ;
    END
  END la_data_in[31]
  PIN la_data_in[32]
    DIRECTION INPUT ;
    USE SIGNAL ;
    PORT
      LAYER met2 ;
        RECT 519.430 0.000 519.710 4.000 ;
    END
  END la_data_in[32]
  PIN la_data_in[33]
    DIRECTION INPUT ;
    USE SIGNAL ;
    PORT
      LAYER met2 ;
        RECT 527.250 0.000 527.530 4.000 ;
    END
  END la_data_in[33]
  PIN la_data_in[34]
    DIRECTION INPUT ;
    USE SIGNAL ;
    PORT
      LAYER met2 ;
        RECT 534.610 0.000 534.890 4.000 ;
    END
  END la_data_in[34]
  PIN la_data_in[35]
    DIRECTION INPUT ;
    USE SIGNAL ;
    PORT
      LAYER met2 ;
        RECT 542.430 0.000 542.710 4.000 ;
    END
  END la_data_in[35]
  PIN la_data_in[36]
    DIRECTION INPUT ;
    USE SIGNAL ;
    PORT
      LAYER met2 ;
        RECT 550.250 0.000 550.530 4.000 ;
    END
  END la_data_in[36]
  PIN la_data_in[37]
    DIRECTION INPUT ;
    USE SIGNAL ;
    PORT
      LAYER met2 ;
        RECT 558.070 0.000 558.350 4.000 ;
    END
  END la_data_in[37]
  PIN la_data_in[38]
    DIRECTION INPUT ;
    USE SIGNAL ;
    PORT
      LAYER met2 ;
        RECT 565.430 0.000 565.710 4.000 ;
    END
  END la_data_in[38]
  PIN la_data_in[39]
    DIRECTION INPUT ;
    USE SIGNAL ;
    PORT
      LAYER met2 ;
        RECT 573.250 0.000 573.530 4.000 ;
    END
  END la_data_in[39]
  PIN la_data_in[3]
    DIRECTION INPUT ;
    USE SIGNAL ;
    PORT
      LAYER met2 ;
        RECT 295.870 0.000 296.150 4.000 ;
    END
  END la_data_in[3]
  PIN la_data_in[40]
    DIRECTION INPUT ;
    USE SIGNAL ;
    PORT
      LAYER met2 ;
        RECT 581.070 0.000 581.350 4.000 ;
    END
  END la_data_in[40]
  PIN la_data_in[41]
    DIRECTION INPUT ;
    USE SIGNAL ;
    PORT
      LAYER met2 ;
        RECT 588.890 0.000 589.170 4.000 ;
    END
  END la_data_in[41]
  PIN la_data_in[42]
    DIRECTION INPUT ;
    USE SIGNAL ;
    PORT
      LAYER met2 ;
        RECT 596.250 0.000 596.530 4.000 ;
    END
  END la_data_in[42]
  PIN la_data_in[43]
    DIRECTION INPUT ;
    USE SIGNAL ;
    PORT
      LAYER met2 ;
        RECT 604.070 0.000 604.350 4.000 ;
    END
  END la_data_in[43]
  PIN la_data_in[44]
    DIRECTION INPUT ;
    USE SIGNAL ;
    PORT
      LAYER met2 ;
        RECT 611.890 0.000 612.170 4.000 ;
    END
  END la_data_in[44]
  PIN la_data_in[45]
    DIRECTION INPUT ;
    USE SIGNAL ;
    PORT
      LAYER met2 ;
        RECT 619.710 0.000 619.990 4.000 ;
    END
  END la_data_in[45]
  PIN la_data_in[46]
    DIRECTION INPUT ;
    USE SIGNAL ;
    PORT
      LAYER met2 ;
        RECT 627.070 0.000 627.350 4.000 ;
    END
  END la_data_in[46]
  PIN la_data_in[47]
    DIRECTION INPUT ;
    USE SIGNAL ;
    PORT
      LAYER met2 ;
        RECT 634.890 0.000 635.170 4.000 ;
    END
  END la_data_in[47]
  PIN la_data_in[48]
    DIRECTION INPUT ;
    USE SIGNAL ;
    PORT
      LAYER met2 ;
        RECT 642.710 0.000 642.990 4.000 ;
    END
  END la_data_in[48]
  PIN la_data_in[49]
    DIRECTION INPUT ;
    USE SIGNAL ;
    PORT
      LAYER met2 ;
        RECT 650.530 0.000 650.810 4.000 ;
    END
  END la_data_in[49]
  PIN la_data_in[4]
    DIRECTION INPUT ;
    USE SIGNAL ;
    PORT
      LAYER met2 ;
        RECT 303.690 0.000 303.970 4.000 ;
    END
  END la_data_in[4]
  PIN la_data_in[50]
    DIRECTION INPUT ;
    USE SIGNAL ;
    PORT
      LAYER met2 ;
        RECT 657.890 0.000 658.170 4.000 ;
    END
  END la_data_in[50]
  PIN la_data_in[51]
    DIRECTION INPUT ;
    USE SIGNAL ;
    PORT
      LAYER met2 ;
        RECT 665.710 0.000 665.990 4.000 ;
    END
  END la_data_in[51]
  PIN la_data_in[52]
    DIRECTION INPUT ;
    USE SIGNAL ;
    PORT
      LAYER met2 ;
        RECT 673.530 0.000 673.810 4.000 ;
    END
  END la_data_in[52]
  PIN la_data_in[53]
    DIRECTION INPUT ;
    USE SIGNAL ;
    PORT
      LAYER met2 ;
        RECT 681.350 0.000 681.630 4.000 ;
    END
  END la_data_in[53]
  PIN la_data_in[54]
    DIRECTION INPUT ;
    USE SIGNAL ;
    PORT
      LAYER met2 ;
        RECT 688.710 0.000 688.990 4.000 ;
    END
  END la_data_in[54]
  PIN la_data_in[55]
    DIRECTION INPUT ;
    USE SIGNAL ;
    PORT
      LAYER met2 ;
        RECT 696.530 0.000 696.810 4.000 ;
    END
  END la_data_in[55]
  PIN la_data_in[56]
    DIRECTION INPUT ;
    USE SIGNAL ;
    PORT
      LAYER met2 ;
        RECT 704.350 0.000 704.630 4.000 ;
    END
  END la_data_in[56]
  PIN la_data_in[57]
    DIRECTION INPUT ;
    USE SIGNAL ;
    PORT
      LAYER met2 ;
        RECT 712.170 0.000 712.450 4.000 ;
    END
  END la_data_in[57]
  PIN la_data_in[58]
    DIRECTION INPUT ;
    USE SIGNAL ;
    PORT
      LAYER met2 ;
        RECT 719.530 0.000 719.810 4.000 ;
    END
  END la_data_in[58]
  PIN la_data_in[59]
    DIRECTION INPUT ;
    USE SIGNAL ;
    PORT
      LAYER met2 ;
        RECT 727.350 0.000 727.630 4.000 ;
    END
  END la_data_in[59]
  PIN la_data_in[5]
    DIRECTION INPUT ;
    USE SIGNAL ;
    PORT
      LAYER met2 ;
        RECT 311.510 0.000 311.790 4.000 ;
    END
  END la_data_in[5]
  PIN la_data_in[60]
    DIRECTION INPUT ;
    USE SIGNAL ;
    PORT
      LAYER met2 ;
        RECT 735.170 0.000 735.450 4.000 ;
    END
  END la_data_in[60]
  PIN la_data_in[61]
    DIRECTION INPUT ;
    USE SIGNAL ;
    PORT
      LAYER met2 ;
        RECT 742.990 0.000 743.270 4.000 ;
    END
  END la_data_in[61]
  PIN la_data_in[62]
    DIRECTION INPUT ;
    USE SIGNAL ;
    PORT
      LAYER met2 ;
        RECT 750.350 0.000 750.630 4.000 ;
    END
  END la_data_in[62]
  PIN la_data_in[63]
    DIRECTION INPUT ;
    USE SIGNAL ;
    PORT
      LAYER met2 ;
        RECT 758.170 0.000 758.450 4.000 ;
    END
  END la_data_in[63]
  PIN la_data_in[64]
    DIRECTION INPUT ;
    USE SIGNAL ;
    PORT
      LAYER met2 ;
        RECT 765.990 0.000 766.270 4.000 ;
    END
  END la_data_in[64]
  PIN la_data_in[65]
    DIRECTION INPUT ;
    USE SIGNAL ;
    PORT
      LAYER met2 ;
        RECT 773.810 0.000 774.090 4.000 ;
    END
  END la_data_in[65]
  PIN la_data_in[66]
    DIRECTION INPUT ;
    USE SIGNAL ;
    PORT
      LAYER met2 ;
        RECT 781.170 0.000 781.450 4.000 ;
    END
  END la_data_in[66]
  PIN la_data_in[67]
    DIRECTION INPUT ;
    USE SIGNAL ;
    PORT
      LAYER met2 ;
        RECT 788.990 0.000 789.270 4.000 ;
    END
  END la_data_in[67]
  PIN la_data_in[68]
    DIRECTION INPUT ;
    USE SIGNAL ;
    PORT
      LAYER met2 ;
        RECT 796.810 0.000 797.090 4.000 ;
    END
  END la_data_in[68]
  PIN la_data_in[69]
    DIRECTION INPUT ;
    USE SIGNAL ;
    PORT
      LAYER met2 ;
        RECT 804.630 0.000 804.910 4.000 ;
    END
  END la_data_in[69]
  PIN la_data_in[6]
    DIRECTION INPUT ;
    USE SIGNAL ;
    PORT
      LAYER met2 ;
        RECT 319.330 0.000 319.610 4.000 ;
    END
  END la_data_in[6]
  PIN la_data_in[70]
    DIRECTION INPUT ;
    USE SIGNAL ;
    PORT
      LAYER met2 ;
        RECT 811.990 0.000 812.270 4.000 ;
    END
  END la_data_in[70]
  PIN la_data_in[71]
    DIRECTION INPUT ;
    USE SIGNAL ;
    PORT
      LAYER met2 ;
        RECT 819.810 0.000 820.090 4.000 ;
    END
  END la_data_in[71]
  PIN la_data_in[72]
    DIRECTION INPUT ;
    USE SIGNAL ;
    PORT
      LAYER met2 ;
        RECT 827.630 0.000 827.910 4.000 ;
    END
  END la_data_in[72]
  PIN la_data_in[73]
    DIRECTION INPUT ;
    USE SIGNAL ;
    PORT
      LAYER met2 ;
        RECT 835.450 0.000 835.730 4.000 ;
    END
  END la_data_in[73]
  PIN la_data_in[74]
    DIRECTION INPUT ;
    USE SIGNAL ;
    PORT
      LAYER met2 ;
        RECT 842.810 0.000 843.090 4.000 ;
    END
  END la_data_in[74]
  PIN la_data_in[75]
    DIRECTION INPUT ;
    USE SIGNAL ;
    PORT
      LAYER met2 ;
        RECT 850.630 0.000 850.910 4.000 ;
    END
  END la_data_in[75]
  PIN la_data_in[76]
    DIRECTION INPUT ;
    USE SIGNAL ;
    PORT
      LAYER met2 ;
        RECT 858.450 0.000 858.730 4.000 ;
    END
  END la_data_in[76]
  PIN la_data_in[77]
    DIRECTION INPUT ;
    USE SIGNAL ;
    PORT
      LAYER met2 ;
        RECT 866.270 0.000 866.550 4.000 ;
    END
  END la_data_in[77]
  PIN la_data_in[78]
    DIRECTION INPUT ;
    USE SIGNAL ;
    PORT
      LAYER met2 ;
        RECT 873.630 0.000 873.910 4.000 ;
    END
  END la_data_in[78]
  PIN la_data_in[79]
    DIRECTION INPUT ;
    USE SIGNAL ;
    PORT
      LAYER met2 ;
        RECT 881.450 0.000 881.730 4.000 ;
    END
  END la_data_in[79]
  PIN la_data_in[7]
    DIRECTION INPUT ;
    USE SIGNAL ;
    PORT
      LAYER met2 ;
        RECT 326.690 0.000 326.970 4.000 ;
    END
  END la_data_in[7]
  PIN la_data_in[80]
    DIRECTION INPUT ;
    USE SIGNAL ;
    PORT
      LAYER met2 ;
        RECT 889.270 0.000 889.550 4.000 ;
    END
  END la_data_in[80]
  PIN la_data_in[81]
    DIRECTION INPUT ;
    USE SIGNAL ;
    PORT
      LAYER met2 ;
        RECT 896.630 0.000 896.910 4.000 ;
    END
  END la_data_in[81]
  PIN la_data_in[82]
    DIRECTION INPUT ;
    USE SIGNAL ;
    PORT
      LAYER met2 ;
        RECT 904.450 0.000 904.730 4.000 ;
    END
  END la_data_in[82]
  PIN la_data_in[83]
    DIRECTION INPUT ;
    USE SIGNAL ;
    PORT
      LAYER met2 ;
        RECT 912.270 0.000 912.550 4.000 ;
    END
  END la_data_in[83]
  PIN la_data_in[84]
    DIRECTION INPUT ;
    USE SIGNAL ;
    PORT
      LAYER met2 ;
        RECT 920.090 0.000 920.370 4.000 ;
    END
  END la_data_in[84]
  PIN la_data_in[85]
    DIRECTION INPUT ;
    USE SIGNAL ;
    PORT
      LAYER met2 ;
        RECT 927.450 0.000 927.730 4.000 ;
    END
  END la_data_in[85]
  PIN la_data_in[86]
    DIRECTION INPUT ;
    USE SIGNAL ;
    PORT
      LAYER met2 ;
        RECT 935.270 0.000 935.550 4.000 ;
    END
  END la_data_in[86]
  PIN la_data_in[87]
    DIRECTION INPUT ;
    USE SIGNAL ;
    PORT
      LAYER met2 ;
        RECT 943.090 0.000 943.370 4.000 ;
    END
  END la_data_in[87]
  PIN la_data_in[88]
    DIRECTION INPUT ;
    USE SIGNAL ;
    PORT
      LAYER met2 ;
        RECT 950.910 0.000 951.190 4.000 ;
    END
  END la_data_in[88]
  PIN la_data_in[89]
    DIRECTION INPUT ;
    USE SIGNAL ;
    PORT
      LAYER met2 ;
        RECT 958.270 0.000 958.550 4.000 ;
    END
  END la_data_in[89]
  PIN la_data_in[8]
    DIRECTION INPUT ;
    USE SIGNAL ;
    PORT
      LAYER met2 ;
        RECT 334.510 0.000 334.790 4.000 ;
    END
  END la_data_in[8]
  PIN la_data_in[90]
    DIRECTION INPUT ;
    USE SIGNAL ;
    PORT
      LAYER met2 ;
        RECT 966.090 0.000 966.370 4.000 ;
    END
  END la_data_in[90]
  PIN la_data_in[91]
    DIRECTION INPUT ;
    USE SIGNAL ;
    PORT
      LAYER met2 ;
        RECT 973.910 0.000 974.190 4.000 ;
    END
  END la_data_in[91]
  PIN la_data_in[92]
    DIRECTION INPUT ;
    USE SIGNAL ;
    PORT
      LAYER met2 ;
        RECT 981.730 0.000 982.010 4.000 ;
    END
  END la_data_in[92]
  PIN la_data_in[93]
    DIRECTION INPUT ;
    USE SIGNAL ;
    PORT
      LAYER met2 ;
        RECT 989.090 0.000 989.370 4.000 ;
    END
  END la_data_in[93]
  PIN la_data_in[94]
    DIRECTION INPUT ;
    USE SIGNAL ;
    PORT
      LAYER met2 ;
        RECT 996.910 0.000 997.190 4.000 ;
    END
  END la_data_in[94]
  PIN la_data_in[95]
    DIRECTION INPUT ;
    USE SIGNAL ;
    PORT
      LAYER met2 ;
        RECT 1004.730 0.000 1005.010 4.000 ;
    END
  END la_data_in[95]
  PIN la_data_in[96]
    DIRECTION INPUT ;
    USE SIGNAL ;
    PORT
      LAYER met2 ;
        RECT 1012.550 0.000 1012.830 4.000 ;
    END
  END la_data_in[96]
  PIN la_data_in[97]
    DIRECTION INPUT ;
    USE SIGNAL ;
    PORT
      LAYER met2 ;
        RECT 1019.910 0.000 1020.190 4.000 ;
    END
  END la_data_in[97]
  PIN la_data_in[98]
    DIRECTION INPUT ;
    USE SIGNAL ;
    PORT
      LAYER met2 ;
        RECT 1027.730 0.000 1028.010 4.000 ;
    END
  END la_data_in[98]
  PIN la_data_in[99]
    DIRECTION INPUT ;
    USE SIGNAL ;
    PORT
      LAYER met2 ;
        RECT 1035.550 0.000 1035.830 4.000 ;
    END
  END la_data_in[99]
  PIN la_data_in[9]
    DIRECTION INPUT ;
    USE SIGNAL ;
    PORT
      LAYER met2 ;
        RECT 342.330 0.000 342.610 4.000 ;
    END
  END la_data_in[9]
  PIN la_data_out[0]
    DIRECTION OUTPUT TRISTATE ;
    USE SIGNAL ;
    PORT
      LAYER met2 ;
        RECT 275.630 0.000 275.910 4.000 ;
    END
  END la_data_out[0]
  PIN la_data_out[100]
    DIRECTION OUTPUT TRISTATE ;
    USE SIGNAL ;
    PORT
      LAYER met2 ;
        RECT 1045.670 0.000 1045.950 4.000 ;
    END
  END la_data_out[100]
  PIN la_data_out[101]
    DIRECTION OUTPUT TRISTATE ;
    USE SIGNAL ;
    PORT
      LAYER met2 ;
        RECT 1053.490 0.000 1053.770 4.000 ;
    END
  END la_data_out[101]
  PIN la_data_out[102]
    DIRECTION OUTPUT TRISTATE ;
    USE SIGNAL ;
    PORT
      LAYER met2 ;
        RECT 1061.310 0.000 1061.590 4.000 ;
    END
  END la_data_out[102]
  PIN la_data_out[103]
    DIRECTION OUTPUT TRISTATE ;
    USE SIGNAL ;
    PORT
      LAYER met2 ;
        RECT 1068.670 0.000 1068.950 4.000 ;
    END
  END la_data_out[103]
  PIN la_data_out[104]
    DIRECTION OUTPUT TRISTATE ;
    USE SIGNAL ;
    PORT
      LAYER met2 ;
        RECT 1076.490 0.000 1076.770 4.000 ;
    END
  END la_data_out[104]
  PIN la_data_out[105]
    DIRECTION OUTPUT TRISTATE ;
    USE SIGNAL ;
    PORT
      LAYER met2 ;
        RECT 1084.310 0.000 1084.590 4.000 ;
    END
  END la_data_out[105]
  PIN la_data_out[106]
    DIRECTION OUTPUT TRISTATE ;
    USE SIGNAL ;
    PORT
      LAYER met2 ;
        RECT 1092.130 0.000 1092.410 4.000 ;
    END
  END la_data_out[106]
  PIN la_data_out[107]
    DIRECTION OUTPUT TRISTATE ;
    USE SIGNAL ;
    PORT
      LAYER met2 ;
        RECT 1099.490 0.000 1099.770 4.000 ;
    END
  END la_data_out[107]
  PIN la_data_out[108]
    DIRECTION OUTPUT TRISTATE ;
    USE SIGNAL ;
    PORT
      LAYER met2 ;
        RECT 1107.310 0.000 1107.590 4.000 ;
    END
  END la_data_out[108]
  PIN la_data_out[109]
    DIRECTION OUTPUT TRISTATE ;
    USE SIGNAL ;
    PORT
      LAYER met2 ;
        RECT 1115.130 0.000 1115.410 4.000 ;
    END
  END la_data_out[109]
  PIN la_data_out[10]
    DIRECTION OUTPUT TRISTATE ;
    USE SIGNAL ;
    PORT
      LAYER met2 ;
        RECT 352.450 0.000 352.730 4.000 ;
    END
  END la_data_out[10]
  PIN la_data_out[110]
    DIRECTION OUTPUT TRISTATE ;
    USE SIGNAL ;
    PORT
      LAYER met2 ;
        RECT 1122.950 0.000 1123.230 4.000 ;
    END
  END la_data_out[110]
  PIN la_data_out[111]
    DIRECTION OUTPUT TRISTATE ;
    USE SIGNAL ;
    PORT
      LAYER met2 ;
        RECT 1130.310 0.000 1130.590 4.000 ;
    END
  END la_data_out[111]
  PIN la_data_out[112]
    DIRECTION OUTPUT TRISTATE ;
    USE SIGNAL ;
    PORT
      LAYER met2 ;
        RECT 1138.130 0.000 1138.410 4.000 ;
    END
  END la_data_out[112]
  PIN la_data_out[113]
    DIRECTION OUTPUT TRISTATE ;
    USE SIGNAL ;
    PORT
      LAYER met2 ;
        RECT 1145.950 0.000 1146.230 4.000 ;
    END
  END la_data_out[113]
  PIN la_data_out[114]
    DIRECTION OUTPUT TRISTATE ;
    USE SIGNAL ;
    PORT
      LAYER met2 ;
        RECT 1153.770 0.000 1154.050 4.000 ;
    END
  END la_data_out[114]
  PIN la_data_out[115]
    DIRECTION OUTPUT TRISTATE ;
    USE SIGNAL ;
    PORT
      LAYER met2 ;
        RECT 1161.130 0.000 1161.410 4.000 ;
    END
  END la_data_out[115]
  PIN la_data_out[116]
    DIRECTION OUTPUT TRISTATE ;
    USE SIGNAL ;
    PORT
      LAYER met2 ;
        RECT 1168.950 0.000 1169.230 4.000 ;
    END
  END la_data_out[116]
  PIN la_data_out[117]
    DIRECTION OUTPUT TRISTATE ;
    USE SIGNAL ;
    PORT
      LAYER met2 ;
        RECT 1176.770 0.000 1177.050 4.000 ;
    END
  END la_data_out[117]
  PIN la_data_out[118]
    DIRECTION OUTPUT TRISTATE ;
    USE SIGNAL ;
    PORT
      LAYER met2 ;
        RECT 1184.590 0.000 1184.870 4.000 ;
    END
  END la_data_out[118]
  PIN la_data_out[119]
    DIRECTION OUTPUT TRISTATE ;
    USE SIGNAL ;
    PORT
      LAYER met2 ;
        RECT 1191.950 0.000 1192.230 4.000 ;
    END
  END la_data_out[119]
  PIN la_data_out[11]
    DIRECTION OUTPUT TRISTATE ;
    USE SIGNAL ;
    PORT
      LAYER met2 ;
        RECT 360.270 0.000 360.550 4.000 ;
    END
  END la_data_out[11]
  PIN la_data_out[120]
    DIRECTION OUTPUT TRISTATE ;
    USE SIGNAL ;
    PORT
      LAYER met2 ;
        RECT 1199.770 0.000 1200.050 4.000 ;
    END
  END la_data_out[120]
  PIN la_data_out[121]
    DIRECTION OUTPUT TRISTATE ;
    USE SIGNAL ;
    PORT
      LAYER met2 ;
        RECT 1207.590 0.000 1207.870 4.000 ;
    END
  END la_data_out[121]
  PIN la_data_out[122]
    DIRECTION OUTPUT TRISTATE ;
    USE SIGNAL ;
    PORT
      LAYER met2 ;
        RECT 1215.410 0.000 1215.690 4.000 ;
    END
  END la_data_out[122]
  PIN la_data_out[123]
    DIRECTION OUTPUT TRISTATE ;
    USE SIGNAL ;
    PORT
      LAYER met2 ;
        RECT 1222.770 0.000 1223.050 4.000 ;
    END
  END la_data_out[123]
  PIN la_data_out[124]
    DIRECTION OUTPUT TRISTATE ;
    USE SIGNAL ;
    PORT
      LAYER met2 ;
        RECT 1230.590 0.000 1230.870 4.000 ;
    END
  END la_data_out[124]
  PIN la_data_out[125]
    DIRECTION OUTPUT TRISTATE ;
    USE SIGNAL ;
    PORT
      LAYER met2 ;
        RECT 1238.410 0.000 1238.690 4.000 ;
    END
  END la_data_out[125]
  PIN la_data_out[126]
    DIRECTION OUTPUT TRISTATE ;
    USE SIGNAL ;
    PORT
      LAYER met2 ;
        RECT 1246.230 0.000 1246.510 4.000 ;
    END
  END la_data_out[126]
  PIN la_data_out[127]
    DIRECTION OUTPUT TRISTATE ;
    USE SIGNAL ;
    PORT
      LAYER met2 ;
        RECT 1253.590 0.000 1253.870 4.000 ;
    END
  END la_data_out[127]
  PIN la_data_out[12]
    DIRECTION OUTPUT TRISTATE ;
    USE SIGNAL ;
    PORT
      LAYER met2 ;
        RECT 368.090 0.000 368.370 4.000 ;
    END
  END la_data_out[12]
  PIN la_data_out[13]
    DIRECTION OUTPUT TRISTATE ;
    USE SIGNAL ;
    PORT
      LAYER met2 ;
        RECT 375.450 0.000 375.730 4.000 ;
    END
  END la_data_out[13]
  PIN la_data_out[14]
    DIRECTION OUTPUT TRISTATE ;
    USE SIGNAL ;
    PORT
      LAYER met2 ;
        RECT 383.270 0.000 383.550 4.000 ;
    END
  END la_data_out[14]
  PIN la_data_out[15]
    DIRECTION OUTPUT TRISTATE ;
    USE SIGNAL ;
    PORT
      LAYER met2 ;
        RECT 391.090 0.000 391.370 4.000 ;
    END
  END la_data_out[15]
  PIN la_data_out[16]
    DIRECTION OUTPUT TRISTATE ;
    USE SIGNAL ;
    PORT
      LAYER met2 ;
        RECT 398.910 0.000 399.190 4.000 ;
    END
  END la_data_out[16]
  PIN la_data_out[17]
    DIRECTION OUTPUT TRISTATE ;
    USE SIGNAL ;
    PORT
      LAYER met2 ;
        RECT 406.270 0.000 406.550 4.000 ;
    END
  END la_data_out[17]
  PIN la_data_out[18]
    DIRECTION OUTPUT TRISTATE ;
    USE SIGNAL ;
    PORT
      LAYER met2 ;
        RECT 414.090 0.000 414.370 4.000 ;
    END
  END la_data_out[18]
  PIN la_data_out[19]
    DIRECTION OUTPUT TRISTATE ;
    USE SIGNAL ;
    PORT
      LAYER met2 ;
        RECT 421.910 0.000 422.190 4.000 ;
    END
  END la_data_out[19]
  PIN la_data_out[1]
    DIRECTION OUTPUT TRISTATE ;
    USE SIGNAL ;
    PORT
      LAYER met2 ;
        RECT 282.990 0.000 283.270 4.000 ;
    END
  END la_data_out[1]
  PIN la_data_out[20]
    DIRECTION OUTPUT TRISTATE ;
    USE SIGNAL ;
    PORT
      LAYER met2 ;
        RECT 429.730 0.000 430.010 4.000 ;
    END
  END la_data_out[20]
  PIN la_data_out[21]
    DIRECTION OUTPUT TRISTATE ;
    USE SIGNAL ;
    PORT
      LAYER met2 ;
        RECT 437.090 0.000 437.370 4.000 ;
    END
  END la_data_out[21]
  PIN la_data_out[22]
    DIRECTION OUTPUT TRISTATE ;
    USE SIGNAL ;
    PORT
      LAYER met2 ;
        RECT 444.910 0.000 445.190 4.000 ;
    END
  END la_data_out[22]
  PIN la_data_out[23]
    DIRECTION OUTPUT TRISTATE ;
    USE SIGNAL ;
    PORT
      LAYER met2 ;
        RECT 452.730 0.000 453.010 4.000 ;
    END
  END la_data_out[23]
  PIN la_data_out[24]
    DIRECTION OUTPUT TRISTATE ;
    USE SIGNAL ;
    PORT
      LAYER met2 ;
        RECT 460.550 0.000 460.830 4.000 ;
    END
  END la_data_out[24]
  PIN la_data_out[25]
    DIRECTION OUTPUT TRISTATE ;
    USE SIGNAL ;
    PORT
      LAYER met2 ;
        RECT 467.910 0.000 468.190 4.000 ;
    END
  END la_data_out[25]
  PIN la_data_out[26]
    DIRECTION OUTPUT TRISTATE ;
    USE SIGNAL ;
    PORT
      LAYER met2 ;
        RECT 475.730 0.000 476.010 4.000 ;
    END
  END la_data_out[26]
  PIN la_data_out[27]
    DIRECTION OUTPUT TRISTATE ;
    USE SIGNAL ;
    PORT
      LAYER met2 ;
        RECT 483.550 0.000 483.830 4.000 ;
    END
  END la_data_out[27]
  PIN la_data_out[28]
    DIRECTION OUTPUT TRISTATE ;
    USE SIGNAL ;
    PORT
      LAYER met2 ;
        RECT 491.370 0.000 491.650 4.000 ;
    END
  END la_data_out[28]
  PIN la_data_out[29]
    DIRECTION OUTPUT TRISTATE ;
    USE SIGNAL ;
    PORT
      LAYER met2 ;
        RECT 498.730 0.000 499.010 4.000 ;
    END
  END la_data_out[29]
  PIN la_data_out[2]
    DIRECTION OUTPUT TRISTATE ;
    USE SIGNAL ;
    PORT
      LAYER met2 ;
        RECT 290.810 0.000 291.090 4.000 ;
    END
  END la_data_out[2]
  PIN la_data_out[30]
    DIRECTION OUTPUT TRISTATE ;
    USE SIGNAL ;
    PORT
      LAYER met2 ;
        RECT 506.550 0.000 506.830 4.000 ;
    END
  END la_data_out[30]
  PIN la_data_out[31]
    DIRECTION OUTPUT TRISTATE ;
    USE SIGNAL ;
    PORT
      LAYER met2 ;
        RECT 514.370 0.000 514.650 4.000 ;
    END
  END la_data_out[31]
  PIN la_data_out[32]
    DIRECTION OUTPUT TRISTATE ;
    USE SIGNAL ;
    PORT
      LAYER met2 ;
        RECT 522.190 0.000 522.470 4.000 ;
    END
  END la_data_out[32]
  PIN la_data_out[33]
    DIRECTION OUTPUT TRISTATE ;
    USE SIGNAL ;
    PORT
      LAYER met2 ;
        RECT 529.550 0.000 529.830 4.000 ;
    END
  END la_data_out[33]
  PIN la_data_out[34]
    DIRECTION OUTPUT TRISTATE ;
    USE SIGNAL ;
    PORT
      LAYER met2 ;
        RECT 537.370 0.000 537.650 4.000 ;
    END
  END la_data_out[34]
  PIN la_data_out[35]
    DIRECTION OUTPUT TRISTATE ;
    USE SIGNAL ;
    PORT
      LAYER met2 ;
        RECT 545.190 0.000 545.470 4.000 ;
    END
  END la_data_out[35]
  PIN la_data_out[36]
    DIRECTION OUTPUT TRISTATE ;
    USE SIGNAL ;
    PORT
      LAYER met2 ;
        RECT 553.010 0.000 553.290 4.000 ;
    END
  END la_data_out[36]
  PIN la_data_out[37]
    DIRECTION OUTPUT TRISTATE ;
    USE SIGNAL ;
    PORT
      LAYER met2 ;
        RECT 560.370 0.000 560.650 4.000 ;
    END
  END la_data_out[37]
  PIN la_data_out[38]
    DIRECTION OUTPUT TRISTATE ;
    USE SIGNAL ;
    PORT
      LAYER met2 ;
        RECT 568.190 0.000 568.470 4.000 ;
    END
  END la_data_out[38]
  PIN la_data_out[39]
    DIRECTION OUTPUT TRISTATE ;
    USE SIGNAL ;
    PORT
      LAYER met2 ;
        RECT 576.010 0.000 576.290 4.000 ;
    END
  END la_data_out[39]
  PIN la_data_out[3]
    DIRECTION OUTPUT TRISTATE ;
    USE SIGNAL ;
    PORT
      LAYER met2 ;
        RECT 298.630 0.000 298.910 4.000 ;
    END
  END la_data_out[3]
  PIN la_data_out[40]
    DIRECTION OUTPUT TRISTATE ;
    USE SIGNAL ;
    PORT
      LAYER met2 ;
        RECT 583.830 0.000 584.110 4.000 ;
    END
  END la_data_out[40]
  PIN la_data_out[41]
    DIRECTION OUTPUT TRISTATE ;
    USE SIGNAL ;
    PORT
      LAYER met2 ;
        RECT 591.190 0.000 591.470 4.000 ;
    END
  END la_data_out[41]
  PIN la_data_out[42]
    DIRECTION OUTPUT TRISTATE ;
    USE SIGNAL ;
    PORT
      LAYER met2 ;
        RECT 599.010 0.000 599.290 4.000 ;
    END
  END la_data_out[42]
  PIN la_data_out[43]
    DIRECTION OUTPUT TRISTATE ;
    USE SIGNAL ;
    PORT
      LAYER met2 ;
        RECT 606.830 0.000 607.110 4.000 ;
    END
  END la_data_out[43]
  PIN la_data_out[44]
    DIRECTION OUTPUT TRISTATE ;
    USE SIGNAL ;
    PORT
      LAYER met2 ;
        RECT 614.650 0.000 614.930 4.000 ;
    END
  END la_data_out[44]
  PIN la_data_out[45]
    DIRECTION OUTPUT TRISTATE ;
    USE SIGNAL ;
    PORT
      LAYER met2 ;
        RECT 622.010 0.000 622.290 4.000 ;
    END
  END la_data_out[45]
  PIN la_data_out[46]
    DIRECTION OUTPUT TRISTATE ;
    USE SIGNAL ;
    PORT
      LAYER met2 ;
        RECT 629.830 0.000 630.110 4.000 ;
    END
  END la_data_out[46]
  PIN la_data_out[47]
    DIRECTION OUTPUT TRISTATE ;
    USE SIGNAL ;
    PORT
      LAYER met2 ;
        RECT 637.650 0.000 637.930 4.000 ;
    END
  END la_data_out[47]
  PIN la_data_out[48]
    DIRECTION OUTPUT TRISTATE ;
    USE SIGNAL ;
    PORT
      LAYER met2 ;
        RECT 645.010 0.000 645.290 4.000 ;
    END
  END la_data_out[48]
  PIN la_data_out[49]
    DIRECTION OUTPUT TRISTATE ;
    USE SIGNAL ;
    PORT
      LAYER met2 ;
        RECT 652.830 0.000 653.110 4.000 ;
    END
  END la_data_out[49]
  PIN la_data_out[4]
    DIRECTION OUTPUT TRISTATE ;
    USE SIGNAL ;
    PORT
      LAYER met2 ;
        RECT 306.450 0.000 306.730 4.000 ;
    END
  END la_data_out[4]
  PIN la_data_out[50]
    DIRECTION OUTPUT TRISTATE ;
    USE SIGNAL ;
    PORT
      LAYER met2 ;
        RECT 660.650 0.000 660.930 4.000 ;
    END
  END la_data_out[50]
  PIN la_data_out[51]
    DIRECTION OUTPUT TRISTATE ;
    USE SIGNAL ;
    PORT
      LAYER met2 ;
        RECT 668.470 0.000 668.750 4.000 ;
    END
  END la_data_out[51]
  PIN la_data_out[52]
    DIRECTION OUTPUT TRISTATE ;
    USE SIGNAL ;
    PORT
      LAYER met2 ;
        RECT 675.830 0.000 676.110 4.000 ;
    END
  END la_data_out[52]
  PIN la_data_out[53]
    DIRECTION OUTPUT TRISTATE ;
    USE SIGNAL ;
    PORT
      LAYER met2 ;
        RECT 683.650 0.000 683.930 4.000 ;
    END
  END la_data_out[53]
  PIN la_data_out[54]
    DIRECTION OUTPUT TRISTATE ;
    USE SIGNAL ;
    PORT
      LAYER met2 ;
        RECT 691.470 0.000 691.750 4.000 ;
    END
  END la_data_out[54]
  PIN la_data_out[55]
    DIRECTION OUTPUT TRISTATE ;
    USE SIGNAL ;
    PORT
      LAYER met2 ;
        RECT 699.290 0.000 699.570 4.000 ;
    END
  END la_data_out[55]
  PIN la_data_out[56]
    DIRECTION OUTPUT TRISTATE ;
    USE SIGNAL ;
    PORT
      LAYER met2 ;
        RECT 706.650 0.000 706.930 4.000 ;
    END
  END la_data_out[56]
  PIN la_data_out[57]
    DIRECTION OUTPUT TRISTATE ;
    USE SIGNAL ;
    PORT
      LAYER met2 ;
        RECT 714.470 0.000 714.750 4.000 ;
    END
  END la_data_out[57]
  PIN la_data_out[58]
    DIRECTION OUTPUT TRISTATE ;
    USE SIGNAL ;
    PORT
      LAYER met2 ;
        RECT 722.290 0.000 722.570 4.000 ;
    END
  END la_data_out[58]
  PIN la_data_out[59]
    DIRECTION OUTPUT TRISTATE ;
    USE SIGNAL ;
    PORT
      LAYER met2 ;
        RECT 730.110 0.000 730.390 4.000 ;
    END
  END la_data_out[59]
  PIN la_data_out[5]
    DIRECTION OUTPUT TRISTATE ;
    USE SIGNAL ;
    PORT
      LAYER met2 ;
        RECT 313.810 0.000 314.090 4.000 ;
    END
  END la_data_out[5]
  PIN la_data_out[60]
    DIRECTION OUTPUT TRISTATE ;
    USE SIGNAL ;
    PORT
      LAYER met2 ;
        RECT 737.470 0.000 737.750 4.000 ;
    END
  END la_data_out[60]
  PIN la_data_out[61]
    DIRECTION OUTPUT TRISTATE ;
    USE SIGNAL ;
    PORT
      LAYER met2 ;
        RECT 745.290 0.000 745.570 4.000 ;
    END
  END la_data_out[61]
  PIN la_data_out[62]
    DIRECTION OUTPUT TRISTATE ;
    USE SIGNAL ;
    PORT
      LAYER met2 ;
        RECT 753.110 0.000 753.390 4.000 ;
    END
  END la_data_out[62]
  PIN la_data_out[63]
    DIRECTION OUTPUT TRISTATE ;
    USE SIGNAL ;
    PORT
      LAYER met2 ;
        RECT 760.930 0.000 761.210 4.000 ;
    END
  END la_data_out[63]
  PIN la_data_out[64]
    DIRECTION OUTPUT TRISTATE ;
    USE SIGNAL ;
    PORT
      LAYER met2 ;
        RECT 768.290 0.000 768.570 4.000 ;
    END
  END la_data_out[64]
  PIN la_data_out[65]
    DIRECTION OUTPUT TRISTATE ;
    USE SIGNAL ;
    PORT
      LAYER met2 ;
        RECT 776.110 0.000 776.390 4.000 ;
    END
  END la_data_out[65]
  PIN la_data_out[66]
    DIRECTION OUTPUT TRISTATE ;
    USE SIGNAL ;
    PORT
      LAYER met2 ;
        RECT 783.930 0.000 784.210 4.000 ;
    END
  END la_data_out[66]
  PIN la_data_out[67]
    DIRECTION OUTPUT TRISTATE ;
    USE SIGNAL ;
    PORT
      LAYER met2 ;
        RECT 791.750 0.000 792.030 4.000 ;
    END
  END la_data_out[67]
  PIN la_data_out[68]
    DIRECTION OUTPUT TRISTATE ;
    USE SIGNAL ;
    PORT
      LAYER met2 ;
        RECT 799.110 0.000 799.390 4.000 ;
    END
  END la_data_out[68]
  PIN la_data_out[69]
    DIRECTION OUTPUT TRISTATE ;
    USE SIGNAL ;
    PORT
      LAYER met2 ;
        RECT 806.930 0.000 807.210 4.000 ;
    END
  END la_data_out[69]
  PIN la_data_out[6]
    DIRECTION OUTPUT TRISTATE ;
    USE SIGNAL ;
    PORT
      LAYER met2 ;
        RECT 321.630 0.000 321.910 4.000 ;
    END
  END la_data_out[6]
  PIN la_data_out[70]
    DIRECTION OUTPUT TRISTATE ;
    USE SIGNAL ;
    PORT
      LAYER met2 ;
        RECT 814.750 0.000 815.030 4.000 ;
    END
  END la_data_out[70]
  PIN la_data_out[71]
    DIRECTION OUTPUT TRISTATE ;
    USE SIGNAL ;
    PORT
      LAYER met2 ;
        RECT 822.570 0.000 822.850 4.000 ;
    END
  END la_data_out[71]
  PIN la_data_out[72]
    DIRECTION OUTPUT TRISTATE ;
    USE SIGNAL ;
    PORT
      LAYER met2 ;
        RECT 829.930 0.000 830.210 4.000 ;
    END
  END la_data_out[72]
  PIN la_data_out[73]
    DIRECTION OUTPUT TRISTATE ;
    USE SIGNAL ;
    PORT
      LAYER met2 ;
        RECT 837.750 0.000 838.030 4.000 ;
    END
  END la_data_out[73]
  PIN la_data_out[74]
    DIRECTION OUTPUT TRISTATE ;
    USE SIGNAL ;
    PORT
      LAYER met2 ;
        RECT 845.570 0.000 845.850 4.000 ;
    END
  END la_data_out[74]
  PIN la_data_out[75]
    DIRECTION OUTPUT TRISTATE ;
    USE SIGNAL ;
    PORT
      LAYER met2 ;
        RECT 853.390 0.000 853.670 4.000 ;
    END
  END la_data_out[75]
  PIN la_data_out[76]
    DIRECTION OUTPUT TRISTATE ;
    USE SIGNAL ;
    PORT
      LAYER met2 ;
        RECT 860.750 0.000 861.030 4.000 ;
    END
  END la_data_out[76]
  PIN la_data_out[77]
    DIRECTION OUTPUT TRISTATE ;
    USE SIGNAL ;
    PORT
      LAYER met2 ;
        RECT 868.570 0.000 868.850 4.000 ;
    END
  END la_data_out[77]
  PIN la_data_out[78]
    DIRECTION OUTPUT TRISTATE ;
    USE SIGNAL ;
    PORT
      LAYER met2 ;
        RECT 876.390 0.000 876.670 4.000 ;
    END
  END la_data_out[78]
  PIN la_data_out[79]
    DIRECTION OUTPUT TRISTATE ;
    USE SIGNAL ;
    PORT
      LAYER met2 ;
        RECT 884.210 0.000 884.490 4.000 ;
    END
  END la_data_out[79]
  PIN la_data_out[7]
    DIRECTION OUTPUT TRISTATE ;
    USE SIGNAL ;
    PORT
      LAYER met2 ;
        RECT 329.450 0.000 329.730 4.000 ;
    END
  END la_data_out[7]
  PIN la_data_out[80]
    DIRECTION OUTPUT TRISTATE ;
    USE SIGNAL ;
    PORT
      LAYER met2 ;
        RECT 891.570 0.000 891.850 4.000 ;
    END
  END la_data_out[80]
  PIN la_data_out[81]
    DIRECTION OUTPUT TRISTATE ;
    USE SIGNAL ;
    PORT
      LAYER met2 ;
        RECT 899.390 0.000 899.670 4.000 ;
    END
  END la_data_out[81]
  PIN la_data_out[82]
    DIRECTION OUTPUT TRISTATE ;
    USE SIGNAL ;
    PORT
      LAYER met2 ;
        RECT 907.210 0.000 907.490 4.000 ;
    END
  END la_data_out[82]
  PIN la_data_out[83]
    DIRECTION OUTPUT TRISTATE ;
    USE SIGNAL ;
    PORT
      LAYER met2 ;
        RECT 915.030 0.000 915.310 4.000 ;
    END
  END la_data_out[83]
  PIN la_data_out[84]
    DIRECTION OUTPUT TRISTATE ;
    USE SIGNAL ;
    PORT
      LAYER met2 ;
        RECT 922.390 0.000 922.670 4.000 ;
    END
  END la_data_out[84]
  PIN la_data_out[85]
    DIRECTION OUTPUT TRISTATE ;
    USE SIGNAL ;
    PORT
      LAYER met2 ;
        RECT 930.210 0.000 930.490 4.000 ;
    END
  END la_data_out[85]
  PIN la_data_out[86]
    DIRECTION OUTPUT TRISTATE ;
    USE SIGNAL ;
    PORT
      LAYER met2 ;
        RECT 938.030 0.000 938.310 4.000 ;
    END
  END la_data_out[86]
  PIN la_data_out[87]
    DIRECTION OUTPUT TRISTATE ;
    USE SIGNAL ;
    PORT
      LAYER met2 ;
        RECT 945.850 0.000 946.130 4.000 ;
    END
  END la_data_out[87]
  PIN la_data_out[88]
    DIRECTION OUTPUT TRISTATE ;
    USE SIGNAL ;
    PORT
      LAYER met2 ;
        RECT 953.210 0.000 953.490 4.000 ;
    END
  END la_data_out[88]
  PIN la_data_out[89]
    DIRECTION OUTPUT TRISTATE ;
    USE SIGNAL ;
    PORT
      LAYER met2 ;
        RECT 961.030 0.000 961.310 4.000 ;
    END
  END la_data_out[89]
  PIN la_data_out[8]
    DIRECTION OUTPUT TRISTATE ;
    USE SIGNAL ;
    PORT
      LAYER met2 ;
        RECT 337.270 0.000 337.550 4.000 ;
    END
  END la_data_out[8]
  PIN la_data_out[90]
    DIRECTION OUTPUT TRISTATE ;
    USE SIGNAL ;
    PORT
      LAYER met2 ;
        RECT 968.850 0.000 969.130 4.000 ;
    END
  END la_data_out[90]
  PIN la_data_out[91]
    DIRECTION OUTPUT TRISTATE ;
    USE SIGNAL ;
    PORT
      LAYER met2 ;
        RECT 976.670 0.000 976.950 4.000 ;
    END
  END la_data_out[91]
  PIN la_data_out[92]
    DIRECTION OUTPUT TRISTATE ;
    USE SIGNAL ;
    PORT
      LAYER met2 ;
        RECT 984.030 0.000 984.310 4.000 ;
    END
  END la_data_out[92]
  PIN la_data_out[93]
    DIRECTION OUTPUT TRISTATE ;
    USE SIGNAL ;
    PORT
      LAYER met2 ;
        RECT 991.850 0.000 992.130 4.000 ;
    END
  END la_data_out[93]
  PIN la_data_out[94]
    DIRECTION OUTPUT TRISTATE ;
    USE SIGNAL ;
    PORT
      LAYER met2 ;
        RECT 999.670 0.000 999.950 4.000 ;
    END
  END la_data_out[94]
  PIN la_data_out[95]
    DIRECTION OUTPUT TRISTATE ;
    USE SIGNAL ;
    PORT
      LAYER met2 ;
        RECT 1007.490 0.000 1007.770 4.000 ;
    END
  END la_data_out[95]
  PIN la_data_out[96]
    DIRECTION OUTPUT TRISTATE ;
    USE SIGNAL ;
    PORT
      LAYER met2 ;
        RECT 1014.850 0.000 1015.130 4.000 ;
    END
  END la_data_out[96]
  PIN la_data_out[97]
    DIRECTION OUTPUT TRISTATE ;
    USE SIGNAL ;
    PORT
      LAYER met2 ;
        RECT 1022.670 0.000 1022.950 4.000 ;
    END
  END la_data_out[97]
  PIN la_data_out[98]
    DIRECTION OUTPUT TRISTATE ;
    USE SIGNAL ;
    PORT
      LAYER met2 ;
        RECT 1030.490 0.000 1030.770 4.000 ;
    END
  END la_data_out[98]
  PIN la_data_out[99]
    DIRECTION OUTPUT TRISTATE ;
    USE SIGNAL ;
    PORT
      LAYER met2 ;
        RECT 1037.850 0.000 1038.130 4.000 ;
    END
  END la_data_out[99]
  PIN la_data_out[9]
    DIRECTION OUTPUT TRISTATE ;
    USE SIGNAL ;
    PORT
      LAYER met2 ;
        RECT 344.630 0.000 344.910 4.000 ;
    END
  END la_data_out[9]
  PIN la_oen[0]
    DIRECTION INPUT ;
    USE SIGNAL ;
    PORT
      LAYER met2 ;
        RECT 277.930 0.000 278.210 4.000 ;
    END
  END la_oen[0]
  PIN la_oen[100]
    DIRECTION INPUT ;
    USE SIGNAL ;
    PORT
      LAYER met2 ;
        RECT 1048.430 0.000 1048.710 4.000 ;
    END
  END la_oen[100]
  PIN la_oen[101]
    DIRECTION INPUT ;
    USE SIGNAL ;
    PORT
      LAYER met2 ;
        RECT 1056.250 0.000 1056.530 4.000 ;
    END
  END la_oen[101]
  PIN la_oen[102]
    DIRECTION INPUT ;
    USE SIGNAL ;
    PORT
      LAYER met2 ;
        RECT 1063.610 0.000 1063.890 4.000 ;
    END
  END la_oen[102]
  PIN la_oen[103]
    DIRECTION INPUT ;
    USE SIGNAL ;
    PORT
      LAYER met2 ;
        RECT 1071.430 0.000 1071.710 4.000 ;
    END
  END la_oen[103]
  PIN la_oen[104]
    DIRECTION INPUT ;
    USE SIGNAL ;
    PORT
      LAYER met2 ;
        RECT 1079.250 0.000 1079.530 4.000 ;
    END
  END la_oen[104]
  PIN la_oen[105]
    DIRECTION INPUT ;
    USE SIGNAL ;
    PORT
      LAYER met2 ;
        RECT 1087.070 0.000 1087.350 4.000 ;
    END
  END la_oen[105]
  PIN la_oen[106]
    DIRECTION INPUT ;
    USE SIGNAL ;
    PORT
      LAYER met2 ;
        RECT 1094.430 0.000 1094.710 4.000 ;
    END
  END la_oen[106]
  PIN la_oen[107]
    DIRECTION INPUT ;
    USE SIGNAL ;
    PORT
      LAYER met2 ;
        RECT 1102.250 0.000 1102.530 4.000 ;
    END
  END la_oen[107]
  PIN la_oen[108]
    DIRECTION INPUT ;
    USE SIGNAL ;
    PORT
      LAYER met2 ;
        RECT 1110.070 0.000 1110.350 4.000 ;
    END
  END la_oen[108]
  PIN la_oen[109]
    DIRECTION INPUT ;
    USE SIGNAL ;
    PORT
      LAYER met2 ;
        RECT 1117.890 0.000 1118.170 4.000 ;
    END
  END la_oen[109]
  PIN la_oen[10]
    DIRECTION INPUT ;
    USE SIGNAL ;
    PORT
      LAYER met2 ;
        RECT 355.210 0.000 355.490 4.000 ;
    END
  END la_oen[10]
  PIN la_oen[110]
    DIRECTION INPUT ;
    USE SIGNAL ;
    PORT
      LAYER met2 ;
        RECT 1125.250 0.000 1125.530 4.000 ;
    END
  END la_oen[110]
  PIN la_oen[111]
    DIRECTION INPUT ;
    USE SIGNAL ;
    PORT
      LAYER met2 ;
        RECT 1133.070 0.000 1133.350 4.000 ;
    END
  END la_oen[111]
  PIN la_oen[112]
    DIRECTION INPUT ;
    USE SIGNAL ;
    PORT
      LAYER met2 ;
        RECT 1140.890 0.000 1141.170 4.000 ;
    END
  END la_oen[112]
  PIN la_oen[113]
    DIRECTION INPUT ;
    USE SIGNAL ;
    PORT
      LAYER met2 ;
        RECT 1148.250 0.000 1148.530 4.000 ;
    END
  END la_oen[113]
  PIN la_oen[114]
    DIRECTION INPUT ;
    USE SIGNAL ;
    PORT
      LAYER met2 ;
        RECT 1156.070 0.000 1156.350 4.000 ;
    END
  END la_oen[114]
  PIN la_oen[115]
    DIRECTION INPUT ;
    USE SIGNAL ;
    PORT
      LAYER met2 ;
        RECT 1163.890 0.000 1164.170 4.000 ;
    END
  END la_oen[115]
  PIN la_oen[116]
    DIRECTION INPUT ;
    USE SIGNAL ;
    PORT
      LAYER met2 ;
        RECT 1171.710 0.000 1171.990 4.000 ;
    END
  END la_oen[116]
  PIN la_oen[117]
    DIRECTION INPUT ;
    USE SIGNAL ;
    PORT
      LAYER met2 ;
        RECT 1179.070 0.000 1179.350 4.000 ;
    END
  END la_oen[117]
  PIN la_oen[118]
    DIRECTION INPUT ;
    USE SIGNAL ;
    PORT
      LAYER met2 ;
        RECT 1186.890 0.000 1187.170 4.000 ;
    END
  END la_oen[118]
  PIN la_oen[119]
    DIRECTION INPUT ;
    USE SIGNAL ;
    PORT
      LAYER met2 ;
        RECT 1194.710 0.000 1194.990 4.000 ;
    END
  END la_oen[119]
  PIN la_oen[11]
    DIRECTION INPUT ;
    USE SIGNAL ;
    PORT
      LAYER met2 ;
        RECT 363.030 0.000 363.310 4.000 ;
    END
  END la_oen[11]
  PIN la_oen[120]
    DIRECTION INPUT ;
    USE SIGNAL ;
    PORT
      LAYER met2 ;
        RECT 1202.530 0.000 1202.810 4.000 ;
    END
  END la_oen[120]
  PIN la_oen[121]
    DIRECTION INPUT ;
    USE SIGNAL ;
    PORT
      LAYER met2 ;
        RECT 1209.890 0.000 1210.170 4.000 ;
    END
  END la_oen[121]
  PIN la_oen[122]
    DIRECTION INPUT ;
    USE SIGNAL ;
    PORT
      LAYER met2 ;
        RECT 1217.710 0.000 1217.990 4.000 ;
    END
  END la_oen[122]
  PIN la_oen[123]
    DIRECTION INPUT ;
    USE SIGNAL ;
    PORT
      LAYER met2 ;
        RECT 1225.530 0.000 1225.810 4.000 ;
    END
  END la_oen[123]
  PIN la_oen[124]
    DIRECTION INPUT ;
    USE SIGNAL ;
    PORT
      LAYER met2 ;
        RECT 1233.350 0.000 1233.630 4.000 ;
    END
  END la_oen[124]
  PIN la_oen[125]
    DIRECTION INPUT ;
    USE SIGNAL ;
    PORT
      LAYER met2 ;
        RECT 1240.710 0.000 1240.990 4.000 ;
    END
  END la_oen[125]
  PIN la_oen[126]
    DIRECTION INPUT ;
    USE SIGNAL ;
    PORT
      LAYER met2 ;
        RECT 1248.530 0.000 1248.810 4.000 ;
    END
  END la_oen[126]
  PIN la_oen[127]
    DIRECTION INPUT ;
    USE SIGNAL ;
    PORT
      LAYER met2 ;
        RECT 1256.350 0.000 1256.630 4.000 ;
    END
  END la_oen[127]
  PIN la_oen[12]
    DIRECTION INPUT ;
    USE SIGNAL ;
    PORT
      LAYER met2 ;
        RECT 370.390 0.000 370.670 4.000 ;
    END
  END la_oen[12]
  PIN la_oen[13]
    DIRECTION INPUT ;
    USE SIGNAL ;
    PORT
      LAYER met2 ;
        RECT 378.210 0.000 378.490 4.000 ;
    END
  END la_oen[13]
  PIN la_oen[14]
    DIRECTION INPUT ;
    USE SIGNAL ;
    PORT
      LAYER met2 ;
        RECT 386.030 0.000 386.310 4.000 ;
    END
  END la_oen[14]
  PIN la_oen[15]
    DIRECTION INPUT ;
    USE SIGNAL ;
    PORT
      LAYER met2 ;
        RECT 393.390 0.000 393.670 4.000 ;
    END
  END la_oen[15]
  PIN la_oen[16]
    DIRECTION INPUT ;
    USE SIGNAL ;
    PORT
      LAYER met2 ;
        RECT 401.210 0.000 401.490 4.000 ;
    END
  END la_oen[16]
  PIN la_oen[17]
    DIRECTION INPUT ;
    USE SIGNAL ;
    PORT
      LAYER met2 ;
        RECT 409.030 0.000 409.310 4.000 ;
    END
  END la_oen[17]
  PIN la_oen[18]
    DIRECTION INPUT ;
    USE SIGNAL ;
    PORT
      LAYER met2 ;
        RECT 416.850 0.000 417.130 4.000 ;
    END
  END la_oen[18]
  PIN la_oen[19]
    DIRECTION INPUT ;
    USE SIGNAL ;
    PORT
      LAYER met2 ;
        RECT 424.210 0.000 424.490 4.000 ;
    END
  END la_oen[19]
  PIN la_oen[1]
    DIRECTION INPUT ;
    USE SIGNAL ;
    PORT
      LAYER met2 ;
        RECT 285.750 0.000 286.030 4.000 ;
    END
  END la_oen[1]
  PIN la_oen[20]
    DIRECTION INPUT ;
    USE SIGNAL ;
    PORT
      LAYER met2 ;
        RECT 432.030 0.000 432.310 4.000 ;
    END
  END la_oen[20]
  PIN la_oen[21]
    DIRECTION INPUT ;
    USE SIGNAL ;
    PORT
      LAYER met2 ;
        RECT 439.850 0.000 440.130 4.000 ;
    END
  END la_oen[21]
  PIN la_oen[22]
    DIRECTION INPUT ;
    USE SIGNAL ;
    PORT
      LAYER met2 ;
        RECT 447.670 0.000 447.950 4.000 ;
    END
  END la_oen[22]
  PIN la_oen[23]
    DIRECTION INPUT ;
    USE SIGNAL ;
    PORT
      LAYER met2 ;
        RECT 455.030 0.000 455.310 4.000 ;
    END
  END la_oen[23]
  PIN la_oen[24]
    DIRECTION INPUT ;
    USE SIGNAL ;
    PORT
      LAYER met2 ;
        RECT 462.850 0.000 463.130 4.000 ;
    END
  END la_oen[24]
  PIN la_oen[25]
    DIRECTION INPUT ;
    USE SIGNAL ;
    PORT
      LAYER met2 ;
        RECT 470.670 0.000 470.950 4.000 ;
    END
  END la_oen[25]
  PIN la_oen[26]
    DIRECTION INPUT ;
    USE SIGNAL ;
    PORT
      LAYER met2 ;
        RECT 478.490 0.000 478.770 4.000 ;
    END
  END la_oen[26]
  PIN la_oen[27]
    DIRECTION INPUT ;
    USE SIGNAL ;
    PORT
      LAYER met2 ;
        RECT 485.850 0.000 486.130 4.000 ;
    END
  END la_oen[27]
  PIN la_oen[28]
    DIRECTION INPUT ;
    USE SIGNAL ;
    PORT
      LAYER met2 ;
        RECT 493.670 0.000 493.950 4.000 ;
    END
  END la_oen[28]
  PIN la_oen[29]
    DIRECTION INPUT ;
    USE SIGNAL ;
    PORT
      LAYER met2 ;
        RECT 501.490 0.000 501.770 4.000 ;
    END
  END la_oen[29]
  PIN la_oen[2]
    DIRECTION INPUT ;
    USE SIGNAL ;
    PORT
      LAYER met2 ;
        RECT 293.570 0.000 293.850 4.000 ;
    END
  END la_oen[2]
  PIN la_oen[30]
    DIRECTION INPUT ;
    USE SIGNAL ;
    PORT
      LAYER met2 ;
        RECT 509.310 0.000 509.590 4.000 ;
    END
  END la_oen[30]
  PIN la_oen[31]
    DIRECTION INPUT ;
    USE SIGNAL ;
    PORT
      LAYER met2 ;
        RECT 516.670 0.000 516.950 4.000 ;
    END
  END la_oen[31]
  PIN la_oen[32]
    DIRECTION INPUT ;
    USE SIGNAL ;
    PORT
      LAYER met2 ;
        RECT 524.490 0.000 524.770 4.000 ;
    END
  END la_oen[32]
  PIN la_oen[33]
    DIRECTION INPUT ;
    USE SIGNAL ;
    PORT
      LAYER met2 ;
        RECT 532.310 0.000 532.590 4.000 ;
    END
  END la_oen[33]
  PIN la_oen[34]
    DIRECTION INPUT ;
    USE SIGNAL ;
    PORT
      LAYER met2 ;
        RECT 540.130 0.000 540.410 4.000 ;
    END
  END la_oen[34]
  PIN la_oen[35]
    DIRECTION INPUT ;
    USE SIGNAL ;
    PORT
      LAYER met2 ;
        RECT 547.490 0.000 547.770 4.000 ;
    END
  END la_oen[35]
  PIN la_oen[36]
    DIRECTION INPUT ;
    USE SIGNAL ;
    PORT
      LAYER met2 ;
        RECT 555.310 0.000 555.590 4.000 ;
    END
  END la_oen[36]
  PIN la_oen[37]
    DIRECTION INPUT ;
    USE SIGNAL ;
    PORT
      LAYER met2 ;
        RECT 563.130 0.000 563.410 4.000 ;
    END
  END la_oen[37]
  PIN la_oen[38]
    DIRECTION INPUT ;
    USE SIGNAL ;
    PORT
      LAYER met2 ;
        RECT 570.950 0.000 571.230 4.000 ;
    END
  END la_oen[38]
  PIN la_oen[39]
    DIRECTION INPUT ;
    USE SIGNAL ;
    PORT
      LAYER met2 ;
        RECT 578.310 0.000 578.590 4.000 ;
    END
  END la_oen[39]
  PIN la_oen[3]
    DIRECTION INPUT ;
    USE SIGNAL ;
    PORT
      LAYER met2 ;
        RECT 301.390 0.000 301.670 4.000 ;
    END
  END la_oen[3]
  PIN la_oen[40]
    DIRECTION INPUT ;
    USE SIGNAL ;
    PORT
      LAYER met2 ;
        RECT 586.130 0.000 586.410 4.000 ;
    END
  END la_oen[40]
  PIN la_oen[41]
    DIRECTION INPUT ;
    USE SIGNAL ;
    PORT
      LAYER met2 ;
        RECT 593.950 0.000 594.230 4.000 ;
    END
  END la_oen[41]
  PIN la_oen[42]
    DIRECTION INPUT ;
    USE SIGNAL ;
    PORT
      LAYER met2 ;
        RECT 601.770 0.000 602.050 4.000 ;
    END
  END la_oen[42]
  PIN la_oen[43]
    DIRECTION INPUT ;
    USE SIGNAL ;
    PORT
      LAYER met2 ;
        RECT 609.130 0.000 609.410 4.000 ;
    END
  END la_oen[43]
  PIN la_oen[44]
    DIRECTION INPUT ;
    USE SIGNAL ;
    PORT
      LAYER met2 ;
        RECT 616.950 0.000 617.230 4.000 ;
    END
  END la_oen[44]
  PIN la_oen[45]
    DIRECTION INPUT ;
    USE SIGNAL ;
    PORT
      LAYER met2 ;
        RECT 624.770 0.000 625.050 4.000 ;
    END
  END la_oen[45]
  PIN la_oen[46]
    DIRECTION INPUT ;
    USE SIGNAL ;
    PORT
      LAYER met2 ;
        RECT 632.590 0.000 632.870 4.000 ;
    END
  END la_oen[46]
  PIN la_oen[47]
    DIRECTION INPUT ;
    USE SIGNAL ;
    PORT
      LAYER met2 ;
        RECT 639.950 0.000 640.230 4.000 ;
    END
  END la_oen[47]
  PIN la_oen[48]
    DIRECTION INPUT ;
    USE SIGNAL ;
    PORT
      LAYER met2 ;
        RECT 647.770 0.000 648.050 4.000 ;
    END
  END la_oen[48]
  PIN la_oen[49]
    DIRECTION INPUT ;
    USE SIGNAL ;
    PORT
      LAYER met2 ;
        RECT 655.590 0.000 655.870 4.000 ;
    END
  END la_oen[49]
  PIN la_oen[4]
    DIRECTION INPUT ;
    USE SIGNAL ;
    PORT
      LAYER met2 ;
        RECT 308.750 0.000 309.030 4.000 ;
    END
  END la_oen[4]
  PIN la_oen[50]
    DIRECTION INPUT ;
    USE SIGNAL ;
    PORT
      LAYER met2 ;
        RECT 663.410 0.000 663.690 4.000 ;
    END
  END la_oen[50]
  PIN la_oen[51]
    DIRECTION INPUT ;
    USE SIGNAL ;
    PORT
      LAYER met2 ;
        RECT 670.770 0.000 671.050 4.000 ;
    END
  END la_oen[51]
  PIN la_oen[52]
    DIRECTION INPUT ;
    USE SIGNAL ;
    PORT
      LAYER met2 ;
        RECT 678.590 0.000 678.870 4.000 ;
    END
  END la_oen[52]
  PIN la_oen[53]
    DIRECTION INPUT ;
    USE SIGNAL ;
    PORT
      LAYER met2 ;
        RECT 686.410 0.000 686.690 4.000 ;
    END
  END la_oen[53]
  PIN la_oen[54]
    DIRECTION INPUT ;
    USE SIGNAL ;
    PORT
      LAYER met2 ;
        RECT 694.230 0.000 694.510 4.000 ;
    END
  END la_oen[54]
  PIN la_oen[55]
    DIRECTION INPUT ;
    USE SIGNAL ;
    PORT
      LAYER met2 ;
        RECT 701.590 0.000 701.870 4.000 ;
    END
  END la_oen[55]
  PIN la_oen[56]
    DIRECTION INPUT ;
    USE SIGNAL ;
    PORT
      LAYER met2 ;
        RECT 709.410 0.000 709.690 4.000 ;
    END
  END la_oen[56]
  PIN la_oen[57]
    DIRECTION INPUT ;
    USE SIGNAL ;
    PORT
      LAYER met2 ;
        RECT 717.230 0.000 717.510 4.000 ;
    END
  END la_oen[57]
  PIN la_oen[58]
    DIRECTION INPUT ;
    USE SIGNAL ;
    PORT
      LAYER met2 ;
        RECT 725.050 0.000 725.330 4.000 ;
    END
  END la_oen[58]
  PIN la_oen[59]
    DIRECTION INPUT ;
    USE SIGNAL ;
    PORT
      LAYER met2 ;
        RECT 732.410 0.000 732.690 4.000 ;
    END
  END la_oen[59]
  PIN la_oen[5]
    DIRECTION INPUT ;
    USE SIGNAL ;
    PORT
      LAYER met2 ;
        RECT 316.570 0.000 316.850 4.000 ;
    END
  END la_oen[5]
  PIN la_oen[60]
    DIRECTION INPUT ;
    USE SIGNAL ;
    PORT
      LAYER met2 ;
        RECT 740.230 0.000 740.510 4.000 ;
    END
  END la_oen[60]
  PIN la_oen[61]
    DIRECTION INPUT ;
    USE SIGNAL ;
    PORT
      LAYER met2 ;
        RECT 748.050 0.000 748.330 4.000 ;
    END
  END la_oen[61]
  PIN la_oen[62]
    DIRECTION INPUT ;
    USE SIGNAL ;
    PORT
      LAYER met2 ;
        RECT 755.870 0.000 756.150 4.000 ;
    END
  END la_oen[62]
  PIN la_oen[63]
    DIRECTION INPUT ;
    USE SIGNAL ;
    PORT
      LAYER met2 ;
        RECT 763.230 0.000 763.510 4.000 ;
    END
  END la_oen[63]
  PIN la_oen[64]
    DIRECTION INPUT ;
    USE SIGNAL ;
    PORT
      LAYER met2 ;
        RECT 771.050 0.000 771.330 4.000 ;
    END
  END la_oen[64]
  PIN la_oen[65]
    DIRECTION INPUT ;
    USE SIGNAL ;
    PORT
      LAYER met2 ;
        RECT 778.870 0.000 779.150 4.000 ;
    END
  END la_oen[65]
  PIN la_oen[66]
    DIRECTION INPUT ;
    USE SIGNAL ;
    PORT
      LAYER met2 ;
        RECT 786.230 0.000 786.510 4.000 ;
    END
  END la_oen[66]
  PIN la_oen[67]
    DIRECTION INPUT ;
    USE SIGNAL ;
    PORT
      LAYER met2 ;
        RECT 794.050 0.000 794.330 4.000 ;
    END
  END la_oen[67]
  PIN la_oen[68]
    DIRECTION INPUT ;
    USE SIGNAL ;
    PORT
      LAYER met2 ;
        RECT 801.870 0.000 802.150 4.000 ;
    END
  END la_oen[68]
  PIN la_oen[69]
    DIRECTION INPUT ;
    USE SIGNAL ;
    PORT
      LAYER met2 ;
        RECT 809.690 0.000 809.970 4.000 ;
    END
  END la_oen[69]
  PIN la_oen[6]
    DIRECTION INPUT ;
    USE SIGNAL ;
    PORT
      LAYER met2 ;
        RECT 324.390 0.000 324.670 4.000 ;
    END
  END la_oen[6]
  PIN la_oen[70]
    DIRECTION INPUT ;
    USE SIGNAL ;
    PORT
      LAYER met2 ;
        RECT 817.050 0.000 817.330 4.000 ;
    END
  END la_oen[70]
  PIN la_oen[71]
    DIRECTION INPUT ;
    USE SIGNAL ;
    PORT
      LAYER met2 ;
        RECT 824.870 0.000 825.150 4.000 ;
    END
  END la_oen[71]
  PIN la_oen[72]
    DIRECTION INPUT ;
    USE SIGNAL ;
    PORT
      LAYER met2 ;
        RECT 832.690 0.000 832.970 4.000 ;
    END
  END la_oen[72]
  PIN la_oen[73]
    DIRECTION INPUT ;
    USE SIGNAL ;
    PORT
      LAYER met2 ;
        RECT 840.510 0.000 840.790 4.000 ;
    END
  END la_oen[73]
  PIN la_oen[74]
    DIRECTION INPUT ;
    USE SIGNAL ;
    PORT
      LAYER met2 ;
        RECT 847.870 0.000 848.150 4.000 ;
    END
  END la_oen[74]
  PIN la_oen[75]
    DIRECTION INPUT ;
    USE SIGNAL ;
    PORT
      LAYER met2 ;
        RECT 855.690 0.000 855.970 4.000 ;
    END
  END la_oen[75]
  PIN la_oen[76]
    DIRECTION INPUT ;
    USE SIGNAL ;
    PORT
      LAYER met2 ;
        RECT 863.510 0.000 863.790 4.000 ;
    END
  END la_oen[76]
  PIN la_oen[77]
    DIRECTION INPUT ;
    USE SIGNAL ;
    PORT
      LAYER met2 ;
        RECT 871.330 0.000 871.610 4.000 ;
    END
  END la_oen[77]
  PIN la_oen[78]
    DIRECTION INPUT ;
    USE SIGNAL ;
    PORT
      LAYER met2 ;
        RECT 878.690 0.000 878.970 4.000 ;
    END
  END la_oen[78]
  PIN la_oen[79]
    DIRECTION INPUT ;
    USE SIGNAL ;
    PORT
      LAYER met2 ;
        RECT 886.510 0.000 886.790 4.000 ;
    END
  END la_oen[79]
  PIN la_oen[7]
    DIRECTION INPUT ;
    USE SIGNAL ;
    PORT
      LAYER met2 ;
        RECT 332.210 0.000 332.490 4.000 ;
    END
  END la_oen[7]
  PIN la_oen[80]
    DIRECTION INPUT ;
    USE SIGNAL ;
    PORT
      LAYER met2 ;
        RECT 894.330 0.000 894.610 4.000 ;
    END
  END la_oen[80]
  PIN la_oen[81]
    DIRECTION INPUT ;
    USE SIGNAL ;
    PORT
      LAYER met2 ;
        RECT 902.150 0.000 902.430 4.000 ;
    END
  END la_oen[81]
  PIN la_oen[82]
    DIRECTION INPUT ;
    USE SIGNAL ;
    PORT
      LAYER met2 ;
        RECT 909.510 0.000 909.790 4.000 ;
    END
  END la_oen[82]
  PIN la_oen[83]
    DIRECTION INPUT ;
    USE SIGNAL ;
    PORT
      LAYER met2 ;
        RECT 917.330 0.000 917.610 4.000 ;
    END
  END la_oen[83]
  PIN la_oen[84]
    DIRECTION INPUT ;
    USE SIGNAL ;
    PORT
      LAYER met2 ;
        RECT 925.150 0.000 925.430 4.000 ;
    END
  END la_oen[84]
  PIN la_oen[85]
    DIRECTION INPUT ;
    USE SIGNAL ;
    PORT
      LAYER met2 ;
        RECT 932.970 0.000 933.250 4.000 ;
    END
  END la_oen[85]
  PIN la_oen[86]
    DIRECTION INPUT ;
    USE SIGNAL ;
    PORT
      LAYER met2 ;
        RECT 940.330 0.000 940.610 4.000 ;
    END
  END la_oen[86]
  PIN la_oen[87]
    DIRECTION INPUT ;
    USE SIGNAL ;
    PORT
      LAYER met2 ;
        RECT 948.150 0.000 948.430 4.000 ;
    END
  END la_oen[87]
  PIN la_oen[88]
    DIRECTION INPUT ;
    USE SIGNAL ;
    PORT
      LAYER met2 ;
        RECT 955.970 0.000 956.250 4.000 ;
    END
  END la_oen[88]
  PIN la_oen[89]
    DIRECTION INPUT ;
    USE SIGNAL ;
    PORT
      LAYER met2 ;
        RECT 963.790 0.000 964.070 4.000 ;
    END
  END la_oen[89]
  PIN la_oen[8]
    DIRECTION INPUT ;
    USE SIGNAL ;
    PORT
      LAYER met2 ;
        RECT 339.570 0.000 339.850 4.000 ;
    END
  END la_oen[8]
  PIN la_oen[90]
    DIRECTION INPUT ;
    USE SIGNAL ;
    PORT
      LAYER met2 ;
        RECT 971.150 0.000 971.430 4.000 ;
    END
  END la_oen[90]
  PIN la_oen[91]
    DIRECTION INPUT ;
    USE SIGNAL ;
    PORT
      LAYER met2 ;
        RECT 978.970 0.000 979.250 4.000 ;
    END
  END la_oen[91]
  PIN la_oen[92]
    DIRECTION INPUT ;
    USE SIGNAL ;
    PORT
      LAYER met2 ;
        RECT 986.790 0.000 987.070 4.000 ;
    END
  END la_oen[92]
  PIN la_oen[93]
    DIRECTION INPUT ;
    USE SIGNAL ;
    PORT
      LAYER met2 ;
        RECT 994.610 0.000 994.890 4.000 ;
    END
  END la_oen[93]
  PIN la_oen[94]
    DIRECTION INPUT ;
    USE SIGNAL ;
    PORT
      LAYER met2 ;
        RECT 1001.970 0.000 1002.250 4.000 ;
    END
  END la_oen[94]
  PIN la_oen[95]
    DIRECTION INPUT ;
    USE SIGNAL ;
    PORT
      LAYER met2 ;
        RECT 1009.790 0.000 1010.070 4.000 ;
    END
  END la_oen[95]
  PIN la_oen[96]
    DIRECTION INPUT ;
    USE SIGNAL ;
    PORT
      LAYER met2 ;
        RECT 1017.610 0.000 1017.890 4.000 ;
    END
  END la_oen[96]
  PIN la_oen[97]
    DIRECTION INPUT ;
    USE SIGNAL ;
    PORT
      LAYER met2 ;
        RECT 1025.430 0.000 1025.710 4.000 ;
    END
  END la_oen[97]
  PIN la_oen[98]
    DIRECTION INPUT ;
    USE SIGNAL ;
    PORT
      LAYER met2 ;
        RECT 1032.790 0.000 1033.070 4.000 ;
    END
  END la_oen[98]
  PIN la_oen[99]
    DIRECTION INPUT ;
    USE SIGNAL ;
    PORT
      LAYER met2 ;
        RECT 1040.610 0.000 1040.890 4.000 ;
    END
  END la_oen[99]
  PIN la_oen[9]
    DIRECTION INPUT ;
    USE SIGNAL ;
    PORT
      LAYER met2 ;
        RECT 347.390 0.000 347.670 4.000 ;
    END
  END la_oen[9]
  PIN wb_clk_i
    DIRECTION INPUT ;
    USE SIGNAL ;
    PORT
      LAYER met2 ;
        RECT 1.010 0.000 1.290 4.000 ;
    END
  END wb_clk_i
  PIN wb_rst_i
    DIRECTION INPUT ;
    USE SIGNAL ;
    PORT
      LAYER met2 ;
        RECT 3.310 0.000 3.590 4.000 ;
    END
  END wb_rst_i
  PIN wbs_ack_o
    DIRECTION OUTPUT TRISTATE ;
    USE SIGNAL ;
    PORT
      LAYER met2 ;
        RECT 6.070 0.000 6.350 4.000 ;
    END
  END wbs_ack_o
  PIN wbs_adr_i[0]
    DIRECTION INPUT ;
    USE SIGNAL ;
    PORT
      LAYER met2 ;
        RECT 16.190 0.000 16.470 4.000 ;
    END
  END wbs_adr_i[0]
  PIN wbs_adr_i[10]
    DIRECTION INPUT ;
    USE SIGNAL ;
    PORT
      LAYER met2 ;
        RECT 103.590 0.000 103.870 4.000 ;
    END
  END wbs_adr_i[10]
  PIN wbs_adr_i[11]
    DIRECTION INPUT ;
    USE SIGNAL ;
    PORT
      LAYER met2 ;
        RECT 111.410 0.000 111.690 4.000 ;
    END
  END wbs_adr_i[11]
  PIN wbs_adr_i[12]
    DIRECTION INPUT ;
    USE SIGNAL ;
    PORT
      LAYER met2 ;
        RECT 118.770 0.000 119.050 4.000 ;
    END
  END wbs_adr_i[12]
  PIN wbs_adr_i[13]
    DIRECTION INPUT ;
    USE SIGNAL ;
    PORT
      LAYER met2 ;
        RECT 126.590 0.000 126.870 4.000 ;
    END
  END wbs_adr_i[13]
  PIN wbs_adr_i[14]
    DIRECTION INPUT ;
    USE SIGNAL ;
    PORT
      LAYER met2 ;
        RECT 134.410 0.000 134.690 4.000 ;
    END
  END wbs_adr_i[14]
  PIN wbs_adr_i[15]
    DIRECTION INPUT ;
    USE SIGNAL ;
    PORT
      LAYER met2 ;
        RECT 141.770 0.000 142.050 4.000 ;
    END
  END wbs_adr_i[15]
  PIN wbs_adr_i[16]
    DIRECTION INPUT ;
    USE SIGNAL ;
    PORT
      LAYER met2 ;
        RECT 149.590 0.000 149.870 4.000 ;
    END
  END wbs_adr_i[16]
  PIN wbs_adr_i[17]
    DIRECTION INPUT ;
    USE SIGNAL ;
    PORT
      LAYER met2 ;
        RECT 157.410 0.000 157.690 4.000 ;
    END
  END wbs_adr_i[17]
  PIN wbs_adr_i[18]
    DIRECTION INPUT ;
    USE SIGNAL ;
    PORT
      LAYER met2 ;
        RECT 165.230 0.000 165.510 4.000 ;
    END
  END wbs_adr_i[18]
  PIN wbs_adr_i[19]
    DIRECTION INPUT ;
    USE SIGNAL ;
    PORT
      LAYER met2 ;
        RECT 172.590 0.000 172.870 4.000 ;
    END
  END wbs_adr_i[19]
  PIN wbs_adr_i[1]
    DIRECTION INPUT ;
    USE SIGNAL ;
    PORT
      LAYER met2 ;
        RECT 26.310 0.000 26.590 4.000 ;
    END
  END wbs_adr_i[1]
  PIN wbs_adr_i[20]
    DIRECTION INPUT ;
    USE SIGNAL ;
    PORT
      LAYER met2 ;
        RECT 180.410 0.000 180.690 4.000 ;
    END
  END wbs_adr_i[20]
  PIN wbs_adr_i[21]
    DIRECTION INPUT ;
    USE SIGNAL ;
    PORT
      LAYER met2 ;
        RECT 188.230 0.000 188.510 4.000 ;
    END
  END wbs_adr_i[21]
  PIN wbs_adr_i[22]
    DIRECTION INPUT ;
    USE SIGNAL ;
    PORT
      LAYER met2 ;
        RECT 196.050 0.000 196.330 4.000 ;
    END
  END wbs_adr_i[22]
  PIN wbs_adr_i[23]
    DIRECTION INPUT ;
    USE SIGNAL ;
    PORT
      LAYER met2 ;
        RECT 203.410 0.000 203.690 4.000 ;
    END
  END wbs_adr_i[23]
  PIN wbs_adr_i[24]
    DIRECTION INPUT ;
    USE SIGNAL ;
    PORT
      LAYER met2 ;
        RECT 211.230 0.000 211.510 4.000 ;
    END
  END wbs_adr_i[24]
  PIN wbs_adr_i[25]
    DIRECTION INPUT ;
    USE SIGNAL ;
    PORT
      LAYER met2 ;
        RECT 219.050 0.000 219.330 4.000 ;
    END
  END wbs_adr_i[25]
  PIN wbs_adr_i[26]
    DIRECTION INPUT ;
    USE SIGNAL ;
    PORT
      LAYER met2 ;
        RECT 226.870 0.000 227.150 4.000 ;
    END
  END wbs_adr_i[26]
  PIN wbs_adr_i[27]
    DIRECTION INPUT ;
    USE SIGNAL ;
    PORT
      LAYER met2 ;
        RECT 234.230 0.000 234.510 4.000 ;
    END
  END wbs_adr_i[27]
  PIN wbs_adr_i[28]
    DIRECTION INPUT ;
    USE SIGNAL ;
    PORT
      LAYER met2 ;
        RECT 242.050 0.000 242.330 4.000 ;
    END
  END wbs_adr_i[28]
  PIN wbs_adr_i[29]
    DIRECTION INPUT ;
    USE SIGNAL ;
    PORT
      LAYER met2 ;
        RECT 249.870 0.000 250.150 4.000 ;
    END
  END wbs_adr_i[29]
  PIN wbs_adr_i[2]
    DIRECTION INPUT ;
    USE SIGNAL ;
    PORT
      LAYER met2 ;
        RECT 36.890 0.000 37.170 4.000 ;
    END
  END wbs_adr_i[2]
  PIN wbs_adr_i[30]
    DIRECTION INPUT ;
    USE SIGNAL ;
    PORT
      LAYER met2 ;
        RECT 257.690 0.000 257.970 4.000 ;
    END
  END wbs_adr_i[30]
  PIN wbs_adr_i[31]
    DIRECTION INPUT ;
    USE SIGNAL ;
    PORT
      LAYER met2 ;
        RECT 265.050 0.000 265.330 4.000 ;
    END
  END wbs_adr_i[31]
  PIN wbs_adr_i[3]
    DIRECTION INPUT ;
    USE SIGNAL ;
    PORT
      LAYER met2 ;
        RECT 47.010 0.000 47.290 4.000 ;
    END
  END wbs_adr_i[3]
  PIN wbs_adr_i[4]
    DIRECTION INPUT ;
    USE SIGNAL ;
    PORT
      LAYER met2 ;
        RECT 57.130 0.000 57.410 4.000 ;
    END
  END wbs_adr_i[4]
  PIN wbs_adr_i[5]
    DIRECTION INPUT ;
    USE SIGNAL ;
    PORT
      LAYER met2 ;
        RECT 64.950 0.000 65.230 4.000 ;
    END
  END wbs_adr_i[5]
  PIN wbs_adr_i[6]
    DIRECTION INPUT ;
    USE SIGNAL ;
    PORT
      LAYER met2 ;
        RECT 72.770 0.000 73.050 4.000 ;
    END
  END wbs_adr_i[6]
  PIN wbs_adr_i[7]
    DIRECTION INPUT ;
    USE SIGNAL ;
    PORT
      LAYER met2 ;
        RECT 80.590 0.000 80.870 4.000 ;
    END
  END wbs_adr_i[7]
  PIN wbs_adr_i[8]
    DIRECTION INPUT ;
    USE SIGNAL ;
    PORT
      LAYER met2 ;
        RECT 87.950 0.000 88.230 4.000 ;
    END
  END wbs_adr_i[8]
  PIN wbs_adr_i[9]
    DIRECTION INPUT ;
    USE SIGNAL ;
    PORT
      LAYER met2 ;
        RECT 95.770 0.000 96.050 4.000 ;
    END
  END wbs_adr_i[9]
  PIN wbs_cyc_i
    DIRECTION INPUT ;
    USE SIGNAL ;
    PORT
      LAYER met2 ;
        RECT 8.370 0.000 8.650 4.000 ;
    END
  END wbs_cyc_i
  PIN wbs_dat_i[0]
    DIRECTION INPUT ;
    USE SIGNAL ;
    PORT
      LAYER met2 ;
        RECT 18.950 0.000 19.230 4.000 ;
    END
  END wbs_dat_i[0]
  PIN wbs_dat_i[10]
    DIRECTION INPUT ;
    USE SIGNAL ;
    PORT
      LAYER met2 ;
        RECT 105.890 0.000 106.170 4.000 ;
    END
  END wbs_dat_i[10]
  PIN wbs_dat_i[11]
    DIRECTION INPUT ;
    USE SIGNAL ;
    PORT
      LAYER met2 ;
        RECT 113.710 0.000 113.990 4.000 ;
    END
  END wbs_dat_i[11]
  PIN wbs_dat_i[12]
    DIRECTION INPUT ;
    USE SIGNAL ;
    PORT
      LAYER met2 ;
        RECT 121.530 0.000 121.810 4.000 ;
    END
  END wbs_dat_i[12]
  PIN wbs_dat_i[13]
    DIRECTION INPUT ;
    USE SIGNAL ;
    PORT
      LAYER met2 ;
        RECT 129.350 0.000 129.630 4.000 ;
    END
  END wbs_dat_i[13]
  PIN wbs_dat_i[14]
    DIRECTION INPUT ;
    USE SIGNAL ;
    PORT
      LAYER met2 ;
        RECT 136.710 0.000 136.990 4.000 ;
    END
  END wbs_dat_i[14]
  PIN wbs_dat_i[15]
    DIRECTION INPUT ;
    USE SIGNAL ;
    PORT
      LAYER met2 ;
        RECT 144.530 0.000 144.810 4.000 ;
    END
  END wbs_dat_i[15]
  PIN wbs_dat_i[16]
    DIRECTION INPUT ;
    USE SIGNAL ;
    PORT
      LAYER met2 ;
        RECT 152.350 0.000 152.630 4.000 ;
    END
  END wbs_dat_i[16]
  PIN wbs_dat_i[17]
    DIRECTION INPUT ;
    USE SIGNAL ;
    PORT
      LAYER met2 ;
        RECT 160.170 0.000 160.450 4.000 ;
    END
  END wbs_dat_i[17]
  PIN wbs_dat_i[18]
    DIRECTION INPUT ;
    USE SIGNAL ;
    PORT
      LAYER met2 ;
        RECT 167.530 0.000 167.810 4.000 ;
    END
  END wbs_dat_i[18]
  PIN wbs_dat_i[19]
    DIRECTION INPUT ;
    USE SIGNAL ;
    PORT
      LAYER met2 ;
        RECT 175.350 0.000 175.630 4.000 ;
    END
  END wbs_dat_i[19]
  PIN wbs_dat_i[1]
    DIRECTION INPUT ;
    USE SIGNAL ;
    PORT
      LAYER met2 ;
        RECT 29.070 0.000 29.350 4.000 ;
    END
  END wbs_dat_i[1]
  PIN wbs_dat_i[20]
    DIRECTION INPUT ;
    USE SIGNAL ;
    PORT
      LAYER met2 ;
        RECT 183.170 0.000 183.450 4.000 ;
    END
  END wbs_dat_i[20]
  PIN wbs_dat_i[21]
    DIRECTION INPUT ;
    USE SIGNAL ;
    PORT
      LAYER met2 ;
        RECT 190.990 0.000 191.270 4.000 ;
    END
  END wbs_dat_i[21]
  PIN wbs_dat_i[22]
    DIRECTION INPUT ;
    USE SIGNAL ;
    PORT
      LAYER met2 ;
        RECT 198.350 0.000 198.630 4.000 ;
    END
  END wbs_dat_i[22]
  PIN wbs_dat_i[23]
    DIRECTION INPUT ;
    USE SIGNAL ;
    PORT
      LAYER met2 ;
        RECT 206.170 0.000 206.450 4.000 ;
    END
  END wbs_dat_i[23]
  PIN wbs_dat_i[24]
    DIRECTION INPUT ;
    USE SIGNAL ;
    PORT
      LAYER met2 ;
        RECT 213.990 0.000 214.270 4.000 ;
    END
  END wbs_dat_i[24]
  PIN wbs_dat_i[25]
    DIRECTION INPUT ;
    USE SIGNAL ;
    PORT
      LAYER met2 ;
        RECT 221.810 0.000 222.090 4.000 ;
    END
  END wbs_dat_i[25]
  PIN wbs_dat_i[26]
    DIRECTION INPUT ;
    USE SIGNAL ;
    PORT
      LAYER met2 ;
        RECT 229.170 0.000 229.450 4.000 ;
    END
  END wbs_dat_i[26]
  PIN wbs_dat_i[27]
    DIRECTION INPUT ;
    USE SIGNAL ;
    PORT
      LAYER met2 ;
        RECT 236.990 0.000 237.270 4.000 ;
    END
  END wbs_dat_i[27]
  PIN wbs_dat_i[28]
    DIRECTION INPUT ;
    USE SIGNAL ;
    PORT
      LAYER met2 ;
        RECT 244.810 0.000 245.090 4.000 ;
    END
  END wbs_dat_i[28]
  PIN wbs_dat_i[29]
    DIRECTION INPUT ;
    USE SIGNAL ;
    PORT
      LAYER met2 ;
        RECT 252.630 0.000 252.910 4.000 ;
    END
  END wbs_dat_i[29]
  PIN wbs_dat_i[2]
    DIRECTION INPUT ;
    USE SIGNAL ;
    PORT
      LAYER met2 ;
        RECT 39.190 0.000 39.470 4.000 ;
    END
  END wbs_dat_i[2]
  PIN wbs_dat_i[30]
    DIRECTION INPUT ;
    USE SIGNAL ;
    PORT
      LAYER met2 ;
        RECT 259.990 0.000 260.270 4.000 ;
    END
  END wbs_dat_i[30]
  PIN wbs_dat_i[31]
    DIRECTION INPUT ;
    USE SIGNAL ;
    PORT
      LAYER met2 ;
        RECT 267.810 0.000 268.090 4.000 ;
    END
  END wbs_dat_i[31]
  PIN wbs_dat_i[3]
    DIRECTION INPUT ;
    USE SIGNAL ;
    PORT
      LAYER met2 ;
        RECT 49.770 0.000 50.050 4.000 ;
    END
  END wbs_dat_i[3]
  PIN wbs_dat_i[4]
    DIRECTION INPUT ;
    USE SIGNAL ;
    PORT
      LAYER met2 ;
        RECT 59.890 0.000 60.170 4.000 ;
    END
  END wbs_dat_i[4]
  PIN wbs_dat_i[5]
    DIRECTION INPUT ;
    USE SIGNAL ;
    PORT
      LAYER met2 ;
        RECT 67.710 0.000 67.990 4.000 ;
    END
  END wbs_dat_i[5]
  PIN wbs_dat_i[6]
    DIRECTION INPUT ;
    USE SIGNAL ;
    PORT
      LAYER met2 ;
        RECT 75.070 0.000 75.350 4.000 ;
    END
  END wbs_dat_i[6]
  PIN wbs_dat_i[7]
    DIRECTION INPUT ;
    USE SIGNAL ;
    PORT
      LAYER met2 ;
        RECT 82.890 0.000 83.170 4.000 ;
    END
  END wbs_dat_i[7]
  PIN wbs_dat_i[8]
    DIRECTION INPUT ;
    USE SIGNAL ;
    PORT
      LAYER met2 ;
        RECT 90.710 0.000 90.990 4.000 ;
    END
  END wbs_dat_i[8]
  PIN wbs_dat_i[9]
    DIRECTION INPUT ;
    USE SIGNAL ;
    PORT
      LAYER met2 ;
        RECT 98.530 0.000 98.810 4.000 ;
    END
  END wbs_dat_i[9]
  PIN wbs_dat_o[0]
    DIRECTION OUTPUT TRISTATE ;
    USE SIGNAL ;
    PORT
      LAYER met2 ;
        RECT 21.250 0.000 21.530 4.000 ;
    END
  END wbs_dat_o[0]
  PIN wbs_dat_o[10]
    DIRECTION OUTPUT TRISTATE ;
    USE SIGNAL ;
    PORT
      LAYER met2 ;
        RECT 108.650 0.000 108.930 4.000 ;
    END
  END wbs_dat_o[10]
  PIN wbs_dat_o[11]
    DIRECTION OUTPUT TRISTATE ;
    USE SIGNAL ;
    PORT
      LAYER met2 ;
        RECT 116.470 0.000 116.750 4.000 ;
    END
  END wbs_dat_o[11]
  PIN wbs_dat_o[12]
    DIRECTION OUTPUT TRISTATE ;
    USE SIGNAL ;
    PORT
      LAYER met2 ;
        RECT 123.830 0.000 124.110 4.000 ;
    END
  END wbs_dat_o[12]
  PIN wbs_dat_o[13]
    DIRECTION OUTPUT TRISTATE ;
    USE SIGNAL ;
    PORT
      LAYER met2 ;
        RECT 131.650 0.000 131.930 4.000 ;
    END
  END wbs_dat_o[13]
  PIN wbs_dat_o[14]
    DIRECTION OUTPUT TRISTATE ;
    USE SIGNAL ;
    PORT
      LAYER met2 ;
        RECT 139.470 0.000 139.750 4.000 ;
    END
  END wbs_dat_o[14]
  PIN wbs_dat_o[15]
    DIRECTION OUTPUT TRISTATE ;
    USE SIGNAL ;
    PORT
      LAYER met2 ;
        RECT 147.290 0.000 147.570 4.000 ;
    END
  END wbs_dat_o[15]
  PIN wbs_dat_o[16]
    DIRECTION OUTPUT TRISTATE ;
    USE SIGNAL ;
    PORT
      LAYER met2 ;
        RECT 154.650 0.000 154.930 4.000 ;
    END
  END wbs_dat_o[16]
  PIN wbs_dat_o[17]
    DIRECTION OUTPUT TRISTATE ;
    USE SIGNAL ;
    PORT
      LAYER met2 ;
        RECT 162.470 0.000 162.750 4.000 ;
    END
  END wbs_dat_o[17]
  PIN wbs_dat_o[18]
    DIRECTION OUTPUT TRISTATE ;
    USE SIGNAL ;
    PORT
      LAYER met2 ;
        RECT 170.290 0.000 170.570 4.000 ;
    END
  END wbs_dat_o[18]
  PIN wbs_dat_o[19]
    DIRECTION OUTPUT TRISTATE ;
    USE SIGNAL ;
    PORT
      LAYER met2 ;
        RECT 178.110 0.000 178.390 4.000 ;
    END
  END wbs_dat_o[19]
  PIN wbs_dat_o[1]
    DIRECTION OUTPUT TRISTATE ;
    USE SIGNAL ;
    PORT
      LAYER met2 ;
        RECT 31.370 0.000 31.650 4.000 ;
    END
  END wbs_dat_o[1]
  PIN wbs_dat_o[20]
    DIRECTION OUTPUT TRISTATE ;
    USE SIGNAL ;
    PORT
      LAYER met2 ;
        RECT 185.470 0.000 185.750 4.000 ;
    END
  END wbs_dat_o[20]
  PIN wbs_dat_o[21]
    DIRECTION OUTPUT TRISTATE ;
    USE SIGNAL ;
    PORT
      LAYER met2 ;
        RECT 193.290 0.000 193.570 4.000 ;
    END
  END wbs_dat_o[21]
  PIN wbs_dat_o[22]
    DIRECTION OUTPUT TRISTATE ;
    USE SIGNAL ;
    PORT
      LAYER met2 ;
        RECT 201.110 0.000 201.390 4.000 ;
    END
  END wbs_dat_o[22]
  PIN wbs_dat_o[23]
    DIRECTION OUTPUT TRISTATE ;
    USE SIGNAL ;
    PORT
      LAYER met2 ;
        RECT 208.930 0.000 209.210 4.000 ;
    END
  END wbs_dat_o[23]
  PIN wbs_dat_o[24]
    DIRECTION OUTPUT TRISTATE ;
    USE SIGNAL ;
    PORT
      LAYER met2 ;
        RECT 216.290 0.000 216.570 4.000 ;
    END
  END wbs_dat_o[24]
  PIN wbs_dat_o[25]
    DIRECTION OUTPUT TRISTATE ;
    USE SIGNAL ;
    PORT
      LAYER met2 ;
        RECT 224.110 0.000 224.390 4.000 ;
    END
  END wbs_dat_o[25]
  PIN wbs_dat_o[26]
    DIRECTION OUTPUT TRISTATE ;
    USE SIGNAL ;
    PORT
      LAYER met2 ;
        RECT 231.930 0.000 232.210 4.000 ;
    END
  END wbs_dat_o[26]
  PIN wbs_dat_o[27]
    DIRECTION OUTPUT TRISTATE ;
    USE SIGNAL ;
    PORT
      LAYER met2 ;
        RECT 239.750 0.000 240.030 4.000 ;
    END
  END wbs_dat_o[27]
  PIN wbs_dat_o[28]
    DIRECTION OUTPUT TRISTATE ;
    USE SIGNAL ;
    PORT
      LAYER met2 ;
        RECT 247.110 0.000 247.390 4.000 ;
    END
  END wbs_dat_o[28]
  PIN wbs_dat_o[29]
    DIRECTION OUTPUT TRISTATE ;
    USE SIGNAL ;
    PORT
      LAYER met2 ;
        RECT 254.930 0.000 255.210 4.000 ;
    END
  END wbs_dat_o[29]
  PIN wbs_dat_o[2]
    DIRECTION OUTPUT TRISTATE ;
    USE SIGNAL ;
    PORT
      LAYER met2 ;
        RECT 41.950 0.000 42.230 4.000 ;
    END
  END wbs_dat_o[2]
  PIN wbs_dat_o[30]
    DIRECTION OUTPUT TRISTATE ;
    USE SIGNAL ;
    PORT
      LAYER met2 ;
        RECT 262.750 0.000 263.030 4.000 ;
    END
  END wbs_dat_o[30]
  PIN wbs_dat_o[31]
    DIRECTION OUTPUT TRISTATE ;
    USE SIGNAL ;
    PORT
      LAYER met2 ;
        RECT 270.570 0.000 270.850 4.000 ;
    END
  END wbs_dat_o[31]
  PIN wbs_dat_o[3]
    DIRECTION OUTPUT TRISTATE ;
    USE SIGNAL ;
    PORT
      LAYER met2 ;
        RECT 52.070 0.000 52.350 4.000 ;
    END
  END wbs_dat_o[3]
  PIN wbs_dat_o[4]
    DIRECTION OUTPUT TRISTATE ;
    USE SIGNAL ;
    PORT
      LAYER met2 ;
        RECT 62.190 0.000 62.470 4.000 ;
    END
  END wbs_dat_o[4]
  PIN wbs_dat_o[5]
    DIRECTION OUTPUT TRISTATE ;
    USE SIGNAL ;
    PORT
      LAYER met2 ;
        RECT 70.010 0.000 70.290 4.000 ;
    END
  END wbs_dat_o[5]
  PIN wbs_dat_o[6]
    DIRECTION OUTPUT TRISTATE ;
    USE SIGNAL ;
    PORT
      LAYER met2 ;
        RECT 77.830 0.000 78.110 4.000 ;
    END
  END wbs_dat_o[6]
  PIN wbs_dat_o[7]
    DIRECTION OUTPUT TRISTATE ;
    USE SIGNAL ;
    PORT
      LAYER met2 ;
        RECT 85.650 0.000 85.930 4.000 ;
    END
  END wbs_dat_o[7]
  PIN wbs_dat_o[8]
    DIRECTION OUTPUT TRISTATE ;
    USE SIGNAL ;
    PORT
      LAYER met2 ;
        RECT 93.010 0.000 93.290 4.000 ;
    END
  END wbs_dat_o[8]
  PIN wbs_dat_o[9]
    DIRECTION OUTPUT TRISTATE ;
    USE SIGNAL ;
    PORT
      LAYER met2 ;
        RECT 100.830 0.000 101.110 4.000 ;
    END
  END wbs_dat_o[9]
  PIN wbs_sel_i[0]
    DIRECTION INPUT ;
    USE SIGNAL ;
    PORT
      LAYER met2 ;
        RECT 24.010 0.000 24.290 4.000 ;
    END
  END wbs_sel_i[0]
  PIN wbs_sel_i[1]
    DIRECTION INPUT ;
    USE SIGNAL ;
    PORT
      LAYER met2 ;
        RECT 34.130 0.000 34.410 4.000 ;
    END
  END wbs_sel_i[1]
  PIN wbs_sel_i[2]
    DIRECTION INPUT ;
    USE SIGNAL ;
    PORT
      LAYER met2 ;
        RECT 44.250 0.000 44.530 4.000 ;
    END
  END wbs_sel_i[2]
  PIN wbs_sel_i[3]
    DIRECTION INPUT ;
    USE SIGNAL ;
    PORT
      LAYER met2 ;
        RECT 54.830 0.000 55.110 4.000 ;
    END
  END wbs_sel_i[3]
  PIN wbs_stb_i
    DIRECTION INPUT ;
    USE SIGNAL ;
    PORT
      LAYER met2 ;
        RECT 11.130 0.000 11.410 4.000 ;
    END
  END wbs_stb_i
  PIN wbs_we_i
    DIRECTION INPUT ;
    USE SIGNAL ;
    PORT
      LAYER met2 ;
        RECT 13.430 0.000 13.710 4.000 ;
    END
  END wbs_we_i
  PIN vccd1
    DIRECTION INOUT ;
    USE POWER ;
    PORT
      LAYER met4 ;
        RECT 1249.840 10.640 1251.440 1256.880 ;
    END
  END vccd1
  PIN vccd1
    DIRECTION INOUT ;
    USE POWER ;
    PORT
      LAYER met4 ;
        RECT 1096.240 10.640 1097.840 1256.880 ;
    END
  END vccd1
  PIN vccd1
    DIRECTION INOUT ;
    USE POWER ;
    PORT
      LAYER met4 ;
        RECT 942.640 10.640 944.240 1256.880 ;
    END
  END vccd1
  PIN vccd1
    DIRECTION INOUT ;
    USE POWER ;
    PORT
      LAYER met4 ;
        RECT 789.040 10.640 790.640 1256.880 ;
    END
  END vccd1
  PIN vccd1
    DIRECTION INOUT ;
    USE POWER ;
    PORT
      LAYER met4 ;
        RECT 635.440 10.640 637.040 1256.880 ;
    END
  END vccd1
  PIN vccd1
    DIRECTION INOUT ;
    USE POWER ;
    PORT
      LAYER met4 ;
        RECT 481.840 10.640 483.440 1256.880 ;
    END
  END vccd1
  PIN vccd1
    DIRECTION INOUT ;
    USE POWER ;
    PORT
      LAYER met4 ;
        RECT 328.240 10.640 329.840 1256.880 ;
    END
  END vccd1
  PIN vccd1
    DIRECTION INOUT ;
    USE POWER ;
    PORT
      LAYER met4 ;
        RECT 174.640 10.640 176.240 1256.880 ;
    END
  END vccd1
  PIN vccd1
    DIRECTION INOUT ;
    USE POWER ;
    PORT
      LAYER met4 ;
        RECT 21.040 10.640 22.640 1256.880 ;
    END
  END vccd1
  PIN vssd1
    DIRECTION INOUT ;
    USE GROUND ;
    PORT
      LAYER met4 ;
        RECT 1173.040 10.640 1174.640 1256.880 ;
    END
  END vssd1
  PIN vssd1
    DIRECTION INOUT ;
    USE GROUND ;
    PORT
      LAYER met4 ;
        RECT 1019.440 10.640 1021.040 1256.880 ;
    END
  END vssd1
  PIN vssd1
    DIRECTION INOUT ;
    USE GROUND ;
    PORT
      LAYER met4 ;
        RECT 865.840 10.640 867.440 1256.880 ;
    END
  END vssd1
  PIN vssd1
    DIRECTION INOUT ;
    USE GROUND ;
    PORT
      LAYER met4 ;
        RECT 712.240 10.640 713.840 1256.880 ;
    END
  END vssd1
  PIN vssd1
    DIRECTION INOUT ;
    USE GROUND ;
    PORT
      LAYER met4 ;
        RECT 558.640 10.640 560.240 1256.880 ;
    END
  END vssd1
  PIN vssd1
    DIRECTION INOUT ;
    USE GROUND ;
    PORT
      LAYER met4 ;
        RECT 405.040 10.640 406.640 1256.880 ;
    END
  END vssd1
  PIN vssd1
    DIRECTION INOUT ;
    USE GROUND ;
    PORT
      LAYER met4 ;
        RECT 251.440 10.640 253.040 1256.880 ;
    END
  END vssd1
  PIN vssd1
    DIRECTION INOUT ;
    USE GROUND ;
    PORT
      LAYER met4 ;
        RECT 97.840 10.640 99.440 1256.880 ;
    END
  END vssd1
  PIN vccd2
    DIRECTION INOUT ;
    USE POWER ;
    PORT
      LAYER met4 ;
        RECT 1099.540 10.880 1101.140 1256.640 ;
    END
  END vccd2
  PIN vccd2
    DIRECTION INOUT ;
    USE POWER ;
    PORT
      LAYER met4 ;
        RECT 945.940 10.880 947.540 1256.640 ;
    END
  END vccd2
  PIN vccd2
    DIRECTION INOUT ;
    USE POWER ;
    PORT
      LAYER met4 ;
        RECT 792.340 10.880 793.940 1256.640 ;
    END
  END vccd2
  PIN vccd2
    DIRECTION INOUT ;
    USE POWER ;
    PORT
      LAYER met4 ;
        RECT 638.740 10.880 640.340 1256.640 ;
    END
  END vccd2
  PIN vccd2
    DIRECTION INOUT ;
    USE POWER ;
    PORT
      LAYER met4 ;
        RECT 485.140 10.880 486.740 1256.640 ;
    END
  END vccd2
  PIN vccd2
    DIRECTION INOUT ;
    USE POWER ;
    PORT
      LAYER met4 ;
        RECT 331.540 10.880 333.140 1256.640 ;
    END
  END vccd2
  PIN vccd2
    DIRECTION INOUT ;
    USE POWER ;
    PORT
      LAYER met4 ;
        RECT 177.940 10.880 179.540 1256.640 ;
    END
  END vccd2
  PIN vccd2
    DIRECTION INOUT ;
    USE POWER ;
    PORT
      LAYER met4 ;
        RECT 24.340 10.880 25.940 1256.640 ;
    END
  END vccd2
  PIN vssd2
    DIRECTION INOUT ;
    USE GROUND ;
    PORT
      LAYER met4 ;
        RECT 1176.340 10.880 1177.940 1256.640 ;
    END
  END vssd2
  PIN vssd2
    DIRECTION INOUT ;
    USE GROUND ;
    PORT
      LAYER met4 ;
        RECT 1022.740 10.880 1024.340 1256.640 ;
    END
  END vssd2
  PIN vssd2
    DIRECTION INOUT ;
    USE GROUND ;
    PORT
      LAYER met4 ;
        RECT 869.140 10.880 870.740 1256.640 ;
    END
  END vssd2
  PIN vssd2
    DIRECTION INOUT ;
    USE GROUND ;
    PORT
      LAYER met4 ;
        RECT 715.540 10.880 717.140 1256.640 ;
    END
  END vssd2
  PIN vssd2
    DIRECTION INOUT ;
    USE GROUND ;
    PORT
      LAYER met4 ;
        RECT 561.940 10.880 563.540 1256.640 ;
    END
  END vssd2
  PIN vssd2
    DIRECTION INOUT ;
    USE GROUND ;
    PORT
      LAYER met4 ;
        RECT 408.340 10.880 409.940 1256.640 ;
    END
  END vssd2
  PIN vssd2
    DIRECTION INOUT ;
    USE GROUND ;
    PORT
      LAYER met4 ;
        RECT 254.740 10.880 256.340 1256.640 ;
    END
  END vssd2
  PIN vssd2
    DIRECTION INOUT ;
    USE GROUND ;
    PORT
      LAYER met4 ;
        RECT 101.140 10.880 102.740 1256.640 ;
    END
  END vssd2
  PIN vdda1
    DIRECTION INOUT ;
    USE POWER ;
    PORT
      LAYER met4 ;
        RECT 1102.840 10.880 1104.440 1256.640 ;
    END
  END vdda1
  PIN vdda1
    DIRECTION INOUT ;
    USE POWER ;
    PORT
      LAYER met4 ;
        RECT 949.240 10.880 950.840 1256.640 ;
    END
  END vdda1
  PIN vdda1
    DIRECTION INOUT ;
    USE POWER ;
    PORT
      LAYER met4 ;
        RECT 795.640 10.880 797.240 1256.640 ;
    END
  END vdda1
  PIN vdda1
    DIRECTION INOUT ;
    USE POWER ;
    PORT
      LAYER met4 ;
        RECT 642.040 10.880 643.640 1256.640 ;
    END
  END vdda1
  PIN vdda1
    DIRECTION INOUT ;
    USE POWER ;
    PORT
      LAYER met4 ;
        RECT 488.440 10.880 490.040 1256.640 ;
    END
  END vdda1
  PIN vdda1
    DIRECTION INOUT ;
    USE POWER ;
    PORT
      LAYER met4 ;
        RECT 334.840 10.880 336.440 1256.640 ;
    END
  END vdda1
  PIN vdda1
    DIRECTION INOUT ;
    USE POWER ;
    PORT
      LAYER met4 ;
        RECT 181.240 10.880 182.840 1256.640 ;
    END
  END vdda1
  PIN vdda1
    DIRECTION INOUT ;
    USE POWER ;
    PORT
      LAYER met4 ;
        RECT 27.640 10.880 29.240 1256.640 ;
    END
  END vdda1
  PIN vssa1
    DIRECTION INOUT ;
    USE GROUND ;
    PORT
      LAYER met4 ;
        RECT 1179.640 10.880 1181.240 1256.640 ;
    END
  END vssa1
  PIN vssa1
    DIRECTION INOUT ;
    USE GROUND ;
    PORT
      LAYER met4 ;
        RECT 1026.040 10.880 1027.640 1256.640 ;
    END
  END vssa1
  PIN vssa1
    DIRECTION INOUT ;
    USE GROUND ;
    PORT
      LAYER met4 ;
        RECT 872.440 10.880 874.040 1256.640 ;
    END
  END vssa1
  PIN vssa1
    DIRECTION INOUT ;
    USE GROUND ;
    PORT
      LAYER met4 ;
        RECT 718.840 10.880 720.440 1256.640 ;
    END
  END vssa1
  PIN vssa1
    DIRECTION INOUT ;
    USE GROUND ;
    PORT
      LAYER met4 ;
        RECT 565.240 10.880 566.840 1256.640 ;
    END
  END vssa1
  PIN vssa1
    DIRECTION INOUT ;
    USE GROUND ;
    PORT
      LAYER met4 ;
        RECT 411.640 10.880 413.240 1256.640 ;
    END
  END vssa1
  PIN vssa1
    DIRECTION INOUT ;
    USE GROUND ;
    PORT
      LAYER met4 ;
        RECT 258.040 10.880 259.640 1256.640 ;
    END
  END vssa1
  PIN vssa1
    DIRECTION INOUT ;
    USE GROUND ;
    PORT
      LAYER met4 ;
        RECT 104.440 10.880 106.040 1256.640 ;
    END
  END vssa1
  PIN vdda2
    DIRECTION INOUT ;
    USE POWER ;
    PORT
      LAYER met4 ;
        RECT 1106.140 10.880 1107.740 1256.640 ;
    END
  END vdda2
  PIN vdda2
    DIRECTION INOUT ;
    USE POWER ;
    PORT
      LAYER met4 ;
        RECT 952.540 10.880 954.140 1256.640 ;
    END
  END vdda2
  PIN vdda2
    DIRECTION INOUT ;
    USE POWER ;
    PORT
      LAYER met4 ;
        RECT 798.940 10.880 800.540 1256.640 ;
    END
  END vdda2
  PIN vdda2
    DIRECTION INOUT ;
    USE POWER ;
    PORT
      LAYER met4 ;
        RECT 645.340 10.880 646.940 1256.640 ;
    END
  END vdda2
  PIN vdda2
    DIRECTION INOUT ;
    USE POWER ;
    PORT
      LAYER met4 ;
        RECT 491.740 10.880 493.340 1256.640 ;
    END
  END vdda2
  PIN vdda2
    DIRECTION INOUT ;
    USE POWER ;
    PORT
      LAYER met4 ;
        RECT 338.140 10.880 339.740 1256.640 ;
    END
  END vdda2
  PIN vdda2
    DIRECTION INOUT ;
    USE POWER ;
    PORT
      LAYER met4 ;
        RECT 184.540 10.880 186.140 1256.640 ;
    END
  END vdda2
  PIN vdda2
    DIRECTION INOUT ;
    USE POWER ;
    PORT
      LAYER met4 ;
        RECT 30.940 10.880 32.540 1256.640 ;
    END
  END vdda2
  PIN vssa2
    DIRECTION INOUT ;
    USE GROUND ;
    PORT
      LAYER met4 ;
        RECT 1182.940 10.880 1184.540 1256.640 ;
    END
  END vssa2
  PIN vssa2
    DIRECTION INOUT ;
    USE GROUND ;
    PORT
      LAYER met4 ;
        RECT 1029.340 10.880 1030.940 1256.640 ;
    END
  END vssa2
  PIN vssa2
    DIRECTION INOUT ;
    USE GROUND ;
    PORT
      LAYER met4 ;
        RECT 875.740 10.880 877.340 1256.640 ;
    END
  END vssa2
  PIN vssa2
    DIRECTION INOUT ;
    USE GROUND ;
    PORT
      LAYER met4 ;
        RECT 722.140 10.880 723.740 1256.640 ;
    END
  END vssa2
  PIN vssa2
    DIRECTION INOUT ;
    USE GROUND ;
    PORT
      LAYER met4 ;
        RECT 568.540 10.880 570.140 1256.640 ;
    END
  END vssa2
  PIN vssa2
    DIRECTION INOUT ;
    USE GROUND ;
    PORT
      LAYER met4 ;
        RECT 414.940 10.880 416.540 1256.640 ;
    END
  END vssa2
  PIN vssa2
    DIRECTION INOUT ;
    USE GROUND ;
    PORT
      LAYER met4 ;
        RECT 261.340 10.880 262.940 1256.640 ;
    END
  END vssa2
  PIN vssa2
    DIRECTION INOUT ;
    USE GROUND ;
    PORT
      LAYER met4 ;
        RECT 107.740 10.880 109.340 1256.640 ;
    END
  END vssa2
  OBS
      LAYER li1 ;
        RECT 5.520 10.795 1252.580 1256.725 ;
      LAYER met1 ;
        RECT 0.990 4.460 1253.890 1256.880 ;
      LAYER met2 ;
        RECT 1.020 1264.565 22.810 1264.845 ;
        RECT 23.650 1264.565 69.270 1264.845 ;
        RECT 70.110 1264.565 115.730 1264.845 ;
        RECT 116.570 1264.565 162.190 1264.845 ;
        RECT 163.030 1264.565 209.110 1264.845 ;
        RECT 209.950 1264.565 255.570 1264.845 ;
        RECT 256.410 1264.565 302.030 1264.845 ;
        RECT 302.870 1264.565 348.950 1264.845 ;
        RECT 349.790 1264.565 395.410 1264.845 ;
        RECT 396.250 1264.565 441.870 1264.845 ;
        RECT 442.710 1264.565 488.330 1264.845 ;
        RECT 489.170 1264.565 535.250 1264.845 ;
        RECT 536.090 1264.565 581.710 1264.845 ;
        RECT 582.550 1264.565 628.170 1264.845 ;
        RECT 629.010 1264.565 675.090 1264.845 ;
        RECT 675.930 1264.565 721.550 1264.845 ;
        RECT 722.390 1264.565 768.010 1264.845 ;
        RECT 768.850 1264.565 814.930 1264.845 ;
        RECT 815.770 1264.565 861.390 1264.845 ;
        RECT 862.230 1264.565 907.850 1264.845 ;
        RECT 908.690 1264.565 954.310 1264.845 ;
        RECT 955.150 1264.565 1001.230 1264.845 ;
        RECT 1002.070 1264.565 1047.690 1264.845 ;
        RECT 1048.530 1264.565 1094.150 1264.845 ;
        RECT 1094.990 1264.565 1141.070 1264.845 ;
        RECT 1141.910 1264.565 1187.530 1264.845 ;
        RECT 1188.370 1264.565 1233.990 1264.845 ;
        RECT 1234.830 1264.565 1253.860 1264.845 ;
        RECT 1.020 4.280 1253.860 1264.565 ;
        RECT 1.570 4.000 3.030 4.280 ;
        RECT 3.870 4.000 5.790 4.280 ;
        RECT 6.630 4.000 8.090 4.280 ;
        RECT 8.930 4.000 10.850 4.280 ;
        RECT 11.690 4.000 13.150 4.280 ;
        RECT 13.990 4.000 15.910 4.280 ;
        RECT 16.750 4.000 18.670 4.280 ;
        RECT 19.510 4.000 20.970 4.280 ;
        RECT 21.810 4.000 23.730 4.280 ;
        RECT 24.570 4.000 26.030 4.280 ;
        RECT 26.870 4.000 28.790 4.280 ;
        RECT 29.630 4.000 31.090 4.280 ;
        RECT 31.930 4.000 33.850 4.280 ;
        RECT 34.690 4.000 36.610 4.280 ;
        RECT 37.450 4.000 38.910 4.280 ;
        RECT 39.750 4.000 41.670 4.280 ;
        RECT 42.510 4.000 43.970 4.280 ;
        RECT 44.810 4.000 46.730 4.280 ;
        RECT 47.570 4.000 49.490 4.280 ;
        RECT 50.330 4.000 51.790 4.280 ;
        RECT 52.630 4.000 54.550 4.280 ;
        RECT 55.390 4.000 56.850 4.280 ;
        RECT 57.690 4.000 59.610 4.280 ;
        RECT 60.450 4.000 61.910 4.280 ;
        RECT 62.750 4.000 64.670 4.280 ;
        RECT 65.510 4.000 67.430 4.280 ;
        RECT 68.270 4.000 69.730 4.280 ;
        RECT 70.570 4.000 72.490 4.280 ;
        RECT 73.330 4.000 74.790 4.280 ;
        RECT 75.630 4.000 77.550 4.280 ;
        RECT 78.390 4.000 80.310 4.280 ;
        RECT 81.150 4.000 82.610 4.280 ;
        RECT 83.450 4.000 85.370 4.280 ;
        RECT 86.210 4.000 87.670 4.280 ;
        RECT 88.510 4.000 90.430 4.280 ;
        RECT 91.270 4.000 92.730 4.280 ;
        RECT 93.570 4.000 95.490 4.280 ;
        RECT 96.330 4.000 98.250 4.280 ;
        RECT 99.090 4.000 100.550 4.280 ;
        RECT 101.390 4.000 103.310 4.280 ;
        RECT 104.150 4.000 105.610 4.280 ;
        RECT 106.450 4.000 108.370 4.280 ;
        RECT 109.210 4.000 111.130 4.280 ;
        RECT 111.970 4.000 113.430 4.280 ;
        RECT 114.270 4.000 116.190 4.280 ;
        RECT 117.030 4.000 118.490 4.280 ;
        RECT 119.330 4.000 121.250 4.280 ;
        RECT 122.090 4.000 123.550 4.280 ;
        RECT 124.390 4.000 126.310 4.280 ;
        RECT 127.150 4.000 129.070 4.280 ;
        RECT 129.910 4.000 131.370 4.280 ;
        RECT 132.210 4.000 134.130 4.280 ;
        RECT 134.970 4.000 136.430 4.280 ;
        RECT 137.270 4.000 139.190 4.280 ;
        RECT 140.030 4.000 141.490 4.280 ;
        RECT 142.330 4.000 144.250 4.280 ;
        RECT 145.090 4.000 147.010 4.280 ;
        RECT 147.850 4.000 149.310 4.280 ;
        RECT 150.150 4.000 152.070 4.280 ;
        RECT 152.910 4.000 154.370 4.280 ;
        RECT 155.210 4.000 157.130 4.280 ;
        RECT 157.970 4.000 159.890 4.280 ;
        RECT 160.730 4.000 162.190 4.280 ;
        RECT 163.030 4.000 164.950 4.280 ;
        RECT 165.790 4.000 167.250 4.280 ;
        RECT 168.090 4.000 170.010 4.280 ;
        RECT 170.850 4.000 172.310 4.280 ;
        RECT 173.150 4.000 175.070 4.280 ;
        RECT 175.910 4.000 177.830 4.280 ;
        RECT 178.670 4.000 180.130 4.280 ;
        RECT 180.970 4.000 182.890 4.280 ;
        RECT 183.730 4.000 185.190 4.280 ;
        RECT 186.030 4.000 187.950 4.280 ;
        RECT 188.790 4.000 190.710 4.280 ;
        RECT 191.550 4.000 193.010 4.280 ;
        RECT 193.850 4.000 195.770 4.280 ;
        RECT 196.610 4.000 198.070 4.280 ;
        RECT 198.910 4.000 200.830 4.280 ;
        RECT 201.670 4.000 203.130 4.280 ;
        RECT 203.970 4.000 205.890 4.280 ;
        RECT 206.730 4.000 208.650 4.280 ;
        RECT 209.490 4.000 210.950 4.280 ;
        RECT 211.790 4.000 213.710 4.280 ;
        RECT 214.550 4.000 216.010 4.280 ;
        RECT 216.850 4.000 218.770 4.280 ;
        RECT 219.610 4.000 221.530 4.280 ;
        RECT 222.370 4.000 223.830 4.280 ;
        RECT 224.670 4.000 226.590 4.280 ;
        RECT 227.430 4.000 228.890 4.280 ;
        RECT 229.730 4.000 231.650 4.280 ;
        RECT 232.490 4.000 233.950 4.280 ;
        RECT 234.790 4.000 236.710 4.280 ;
        RECT 237.550 4.000 239.470 4.280 ;
        RECT 240.310 4.000 241.770 4.280 ;
        RECT 242.610 4.000 244.530 4.280 ;
        RECT 245.370 4.000 246.830 4.280 ;
        RECT 247.670 4.000 249.590 4.280 ;
        RECT 250.430 4.000 252.350 4.280 ;
        RECT 253.190 4.000 254.650 4.280 ;
        RECT 255.490 4.000 257.410 4.280 ;
        RECT 258.250 4.000 259.710 4.280 ;
        RECT 260.550 4.000 262.470 4.280 ;
        RECT 263.310 4.000 264.770 4.280 ;
        RECT 265.610 4.000 267.530 4.280 ;
        RECT 268.370 4.000 270.290 4.280 ;
        RECT 271.130 4.000 272.590 4.280 ;
        RECT 273.430 4.000 275.350 4.280 ;
        RECT 276.190 4.000 277.650 4.280 ;
        RECT 278.490 4.000 280.410 4.280 ;
        RECT 281.250 4.000 282.710 4.280 ;
        RECT 283.550 4.000 285.470 4.280 ;
        RECT 286.310 4.000 288.230 4.280 ;
        RECT 289.070 4.000 290.530 4.280 ;
        RECT 291.370 4.000 293.290 4.280 ;
        RECT 294.130 4.000 295.590 4.280 ;
        RECT 296.430 4.000 298.350 4.280 ;
        RECT 299.190 4.000 301.110 4.280 ;
        RECT 301.950 4.000 303.410 4.280 ;
        RECT 304.250 4.000 306.170 4.280 ;
        RECT 307.010 4.000 308.470 4.280 ;
        RECT 309.310 4.000 311.230 4.280 ;
        RECT 312.070 4.000 313.530 4.280 ;
        RECT 314.370 4.000 316.290 4.280 ;
        RECT 317.130 4.000 319.050 4.280 ;
        RECT 319.890 4.000 321.350 4.280 ;
        RECT 322.190 4.000 324.110 4.280 ;
        RECT 324.950 4.000 326.410 4.280 ;
        RECT 327.250 4.000 329.170 4.280 ;
        RECT 330.010 4.000 331.930 4.280 ;
        RECT 332.770 4.000 334.230 4.280 ;
        RECT 335.070 4.000 336.990 4.280 ;
        RECT 337.830 4.000 339.290 4.280 ;
        RECT 340.130 4.000 342.050 4.280 ;
        RECT 342.890 4.000 344.350 4.280 ;
        RECT 345.190 4.000 347.110 4.280 ;
        RECT 347.950 4.000 349.870 4.280 ;
        RECT 350.710 4.000 352.170 4.280 ;
        RECT 353.010 4.000 354.930 4.280 ;
        RECT 355.770 4.000 357.230 4.280 ;
        RECT 358.070 4.000 359.990 4.280 ;
        RECT 360.830 4.000 362.750 4.280 ;
        RECT 363.590 4.000 365.050 4.280 ;
        RECT 365.890 4.000 367.810 4.280 ;
        RECT 368.650 4.000 370.110 4.280 ;
        RECT 370.950 4.000 372.870 4.280 ;
        RECT 373.710 4.000 375.170 4.280 ;
        RECT 376.010 4.000 377.930 4.280 ;
        RECT 378.770 4.000 380.690 4.280 ;
        RECT 381.530 4.000 382.990 4.280 ;
        RECT 383.830 4.000 385.750 4.280 ;
        RECT 386.590 4.000 388.050 4.280 ;
        RECT 388.890 4.000 390.810 4.280 ;
        RECT 391.650 4.000 393.110 4.280 ;
        RECT 393.950 4.000 395.870 4.280 ;
        RECT 396.710 4.000 398.630 4.280 ;
        RECT 399.470 4.000 400.930 4.280 ;
        RECT 401.770 4.000 403.690 4.280 ;
        RECT 404.530 4.000 405.990 4.280 ;
        RECT 406.830 4.000 408.750 4.280 ;
        RECT 409.590 4.000 411.510 4.280 ;
        RECT 412.350 4.000 413.810 4.280 ;
        RECT 414.650 4.000 416.570 4.280 ;
        RECT 417.410 4.000 418.870 4.280 ;
        RECT 419.710 4.000 421.630 4.280 ;
        RECT 422.470 4.000 423.930 4.280 ;
        RECT 424.770 4.000 426.690 4.280 ;
        RECT 427.530 4.000 429.450 4.280 ;
        RECT 430.290 4.000 431.750 4.280 ;
        RECT 432.590 4.000 434.510 4.280 ;
        RECT 435.350 4.000 436.810 4.280 ;
        RECT 437.650 4.000 439.570 4.280 ;
        RECT 440.410 4.000 442.330 4.280 ;
        RECT 443.170 4.000 444.630 4.280 ;
        RECT 445.470 4.000 447.390 4.280 ;
        RECT 448.230 4.000 449.690 4.280 ;
        RECT 450.530 4.000 452.450 4.280 ;
        RECT 453.290 4.000 454.750 4.280 ;
        RECT 455.590 4.000 457.510 4.280 ;
        RECT 458.350 4.000 460.270 4.280 ;
        RECT 461.110 4.000 462.570 4.280 ;
        RECT 463.410 4.000 465.330 4.280 ;
        RECT 466.170 4.000 467.630 4.280 ;
        RECT 468.470 4.000 470.390 4.280 ;
        RECT 471.230 4.000 473.150 4.280 ;
        RECT 473.990 4.000 475.450 4.280 ;
        RECT 476.290 4.000 478.210 4.280 ;
        RECT 479.050 4.000 480.510 4.280 ;
        RECT 481.350 4.000 483.270 4.280 ;
        RECT 484.110 4.000 485.570 4.280 ;
        RECT 486.410 4.000 488.330 4.280 ;
        RECT 489.170 4.000 491.090 4.280 ;
        RECT 491.930 4.000 493.390 4.280 ;
        RECT 494.230 4.000 496.150 4.280 ;
        RECT 496.990 4.000 498.450 4.280 ;
        RECT 499.290 4.000 501.210 4.280 ;
        RECT 502.050 4.000 503.970 4.280 ;
        RECT 504.810 4.000 506.270 4.280 ;
        RECT 507.110 4.000 509.030 4.280 ;
        RECT 509.870 4.000 511.330 4.280 ;
        RECT 512.170 4.000 514.090 4.280 ;
        RECT 514.930 4.000 516.390 4.280 ;
        RECT 517.230 4.000 519.150 4.280 ;
        RECT 519.990 4.000 521.910 4.280 ;
        RECT 522.750 4.000 524.210 4.280 ;
        RECT 525.050 4.000 526.970 4.280 ;
        RECT 527.810 4.000 529.270 4.280 ;
        RECT 530.110 4.000 532.030 4.280 ;
        RECT 532.870 4.000 534.330 4.280 ;
        RECT 535.170 4.000 537.090 4.280 ;
        RECT 537.930 4.000 539.850 4.280 ;
        RECT 540.690 4.000 542.150 4.280 ;
        RECT 542.990 4.000 544.910 4.280 ;
        RECT 545.750 4.000 547.210 4.280 ;
        RECT 548.050 4.000 549.970 4.280 ;
        RECT 550.810 4.000 552.730 4.280 ;
        RECT 553.570 4.000 555.030 4.280 ;
        RECT 555.870 4.000 557.790 4.280 ;
        RECT 558.630 4.000 560.090 4.280 ;
        RECT 560.930 4.000 562.850 4.280 ;
        RECT 563.690 4.000 565.150 4.280 ;
        RECT 565.990 4.000 567.910 4.280 ;
        RECT 568.750 4.000 570.670 4.280 ;
        RECT 571.510 4.000 572.970 4.280 ;
        RECT 573.810 4.000 575.730 4.280 ;
        RECT 576.570 4.000 578.030 4.280 ;
        RECT 578.870 4.000 580.790 4.280 ;
        RECT 581.630 4.000 583.550 4.280 ;
        RECT 584.390 4.000 585.850 4.280 ;
        RECT 586.690 4.000 588.610 4.280 ;
        RECT 589.450 4.000 590.910 4.280 ;
        RECT 591.750 4.000 593.670 4.280 ;
        RECT 594.510 4.000 595.970 4.280 ;
        RECT 596.810 4.000 598.730 4.280 ;
        RECT 599.570 4.000 601.490 4.280 ;
        RECT 602.330 4.000 603.790 4.280 ;
        RECT 604.630 4.000 606.550 4.280 ;
        RECT 607.390 4.000 608.850 4.280 ;
        RECT 609.690 4.000 611.610 4.280 ;
        RECT 612.450 4.000 614.370 4.280 ;
        RECT 615.210 4.000 616.670 4.280 ;
        RECT 617.510 4.000 619.430 4.280 ;
        RECT 620.270 4.000 621.730 4.280 ;
        RECT 622.570 4.000 624.490 4.280 ;
        RECT 625.330 4.000 626.790 4.280 ;
        RECT 627.630 4.000 629.550 4.280 ;
        RECT 630.390 4.000 632.310 4.280 ;
        RECT 633.150 4.000 634.610 4.280 ;
        RECT 635.450 4.000 637.370 4.280 ;
        RECT 638.210 4.000 639.670 4.280 ;
        RECT 640.510 4.000 642.430 4.280 ;
        RECT 643.270 4.000 644.730 4.280 ;
        RECT 645.570 4.000 647.490 4.280 ;
        RECT 648.330 4.000 650.250 4.280 ;
        RECT 651.090 4.000 652.550 4.280 ;
        RECT 653.390 4.000 655.310 4.280 ;
        RECT 656.150 4.000 657.610 4.280 ;
        RECT 658.450 4.000 660.370 4.280 ;
        RECT 661.210 4.000 663.130 4.280 ;
        RECT 663.970 4.000 665.430 4.280 ;
        RECT 666.270 4.000 668.190 4.280 ;
        RECT 669.030 4.000 670.490 4.280 ;
        RECT 671.330 4.000 673.250 4.280 ;
        RECT 674.090 4.000 675.550 4.280 ;
        RECT 676.390 4.000 678.310 4.280 ;
        RECT 679.150 4.000 681.070 4.280 ;
        RECT 681.910 4.000 683.370 4.280 ;
        RECT 684.210 4.000 686.130 4.280 ;
        RECT 686.970 4.000 688.430 4.280 ;
        RECT 689.270 4.000 691.190 4.280 ;
        RECT 692.030 4.000 693.950 4.280 ;
        RECT 694.790 4.000 696.250 4.280 ;
        RECT 697.090 4.000 699.010 4.280 ;
        RECT 699.850 4.000 701.310 4.280 ;
        RECT 702.150 4.000 704.070 4.280 ;
        RECT 704.910 4.000 706.370 4.280 ;
        RECT 707.210 4.000 709.130 4.280 ;
        RECT 709.970 4.000 711.890 4.280 ;
        RECT 712.730 4.000 714.190 4.280 ;
        RECT 715.030 4.000 716.950 4.280 ;
        RECT 717.790 4.000 719.250 4.280 ;
        RECT 720.090 4.000 722.010 4.280 ;
        RECT 722.850 4.000 724.770 4.280 ;
        RECT 725.610 4.000 727.070 4.280 ;
        RECT 727.910 4.000 729.830 4.280 ;
        RECT 730.670 4.000 732.130 4.280 ;
        RECT 732.970 4.000 734.890 4.280 ;
        RECT 735.730 4.000 737.190 4.280 ;
        RECT 738.030 4.000 739.950 4.280 ;
        RECT 740.790 4.000 742.710 4.280 ;
        RECT 743.550 4.000 745.010 4.280 ;
        RECT 745.850 4.000 747.770 4.280 ;
        RECT 748.610 4.000 750.070 4.280 ;
        RECT 750.910 4.000 752.830 4.280 ;
        RECT 753.670 4.000 755.590 4.280 ;
        RECT 756.430 4.000 757.890 4.280 ;
        RECT 758.730 4.000 760.650 4.280 ;
        RECT 761.490 4.000 762.950 4.280 ;
        RECT 763.790 4.000 765.710 4.280 ;
        RECT 766.550 4.000 768.010 4.280 ;
        RECT 768.850 4.000 770.770 4.280 ;
        RECT 771.610 4.000 773.530 4.280 ;
        RECT 774.370 4.000 775.830 4.280 ;
        RECT 776.670 4.000 778.590 4.280 ;
        RECT 779.430 4.000 780.890 4.280 ;
        RECT 781.730 4.000 783.650 4.280 ;
        RECT 784.490 4.000 785.950 4.280 ;
        RECT 786.790 4.000 788.710 4.280 ;
        RECT 789.550 4.000 791.470 4.280 ;
        RECT 792.310 4.000 793.770 4.280 ;
        RECT 794.610 4.000 796.530 4.280 ;
        RECT 797.370 4.000 798.830 4.280 ;
        RECT 799.670 4.000 801.590 4.280 ;
        RECT 802.430 4.000 804.350 4.280 ;
        RECT 805.190 4.000 806.650 4.280 ;
        RECT 807.490 4.000 809.410 4.280 ;
        RECT 810.250 4.000 811.710 4.280 ;
        RECT 812.550 4.000 814.470 4.280 ;
        RECT 815.310 4.000 816.770 4.280 ;
        RECT 817.610 4.000 819.530 4.280 ;
        RECT 820.370 4.000 822.290 4.280 ;
        RECT 823.130 4.000 824.590 4.280 ;
        RECT 825.430 4.000 827.350 4.280 ;
        RECT 828.190 4.000 829.650 4.280 ;
        RECT 830.490 4.000 832.410 4.280 ;
        RECT 833.250 4.000 835.170 4.280 ;
        RECT 836.010 4.000 837.470 4.280 ;
        RECT 838.310 4.000 840.230 4.280 ;
        RECT 841.070 4.000 842.530 4.280 ;
        RECT 843.370 4.000 845.290 4.280 ;
        RECT 846.130 4.000 847.590 4.280 ;
        RECT 848.430 4.000 850.350 4.280 ;
        RECT 851.190 4.000 853.110 4.280 ;
        RECT 853.950 4.000 855.410 4.280 ;
        RECT 856.250 4.000 858.170 4.280 ;
        RECT 859.010 4.000 860.470 4.280 ;
        RECT 861.310 4.000 863.230 4.280 ;
        RECT 864.070 4.000 865.990 4.280 ;
        RECT 866.830 4.000 868.290 4.280 ;
        RECT 869.130 4.000 871.050 4.280 ;
        RECT 871.890 4.000 873.350 4.280 ;
        RECT 874.190 4.000 876.110 4.280 ;
        RECT 876.950 4.000 878.410 4.280 ;
        RECT 879.250 4.000 881.170 4.280 ;
        RECT 882.010 4.000 883.930 4.280 ;
        RECT 884.770 4.000 886.230 4.280 ;
        RECT 887.070 4.000 888.990 4.280 ;
        RECT 889.830 4.000 891.290 4.280 ;
        RECT 892.130 4.000 894.050 4.280 ;
        RECT 894.890 4.000 896.350 4.280 ;
        RECT 897.190 4.000 899.110 4.280 ;
        RECT 899.950 4.000 901.870 4.280 ;
        RECT 902.710 4.000 904.170 4.280 ;
        RECT 905.010 4.000 906.930 4.280 ;
        RECT 907.770 4.000 909.230 4.280 ;
        RECT 910.070 4.000 911.990 4.280 ;
        RECT 912.830 4.000 914.750 4.280 ;
        RECT 915.590 4.000 917.050 4.280 ;
        RECT 917.890 4.000 919.810 4.280 ;
        RECT 920.650 4.000 922.110 4.280 ;
        RECT 922.950 4.000 924.870 4.280 ;
        RECT 925.710 4.000 927.170 4.280 ;
        RECT 928.010 4.000 929.930 4.280 ;
        RECT 930.770 4.000 932.690 4.280 ;
        RECT 933.530 4.000 934.990 4.280 ;
        RECT 935.830 4.000 937.750 4.280 ;
        RECT 938.590 4.000 940.050 4.280 ;
        RECT 940.890 4.000 942.810 4.280 ;
        RECT 943.650 4.000 945.570 4.280 ;
        RECT 946.410 4.000 947.870 4.280 ;
        RECT 948.710 4.000 950.630 4.280 ;
        RECT 951.470 4.000 952.930 4.280 ;
        RECT 953.770 4.000 955.690 4.280 ;
        RECT 956.530 4.000 957.990 4.280 ;
        RECT 958.830 4.000 960.750 4.280 ;
        RECT 961.590 4.000 963.510 4.280 ;
        RECT 964.350 4.000 965.810 4.280 ;
        RECT 966.650 4.000 968.570 4.280 ;
        RECT 969.410 4.000 970.870 4.280 ;
        RECT 971.710 4.000 973.630 4.280 ;
        RECT 974.470 4.000 976.390 4.280 ;
        RECT 977.230 4.000 978.690 4.280 ;
        RECT 979.530 4.000 981.450 4.280 ;
        RECT 982.290 4.000 983.750 4.280 ;
        RECT 984.590 4.000 986.510 4.280 ;
        RECT 987.350 4.000 988.810 4.280 ;
        RECT 989.650 4.000 991.570 4.280 ;
        RECT 992.410 4.000 994.330 4.280 ;
        RECT 995.170 4.000 996.630 4.280 ;
        RECT 997.470 4.000 999.390 4.280 ;
        RECT 1000.230 4.000 1001.690 4.280 ;
        RECT 1002.530 4.000 1004.450 4.280 ;
        RECT 1005.290 4.000 1007.210 4.280 ;
        RECT 1008.050 4.000 1009.510 4.280 ;
        RECT 1010.350 4.000 1012.270 4.280 ;
        RECT 1013.110 4.000 1014.570 4.280 ;
        RECT 1015.410 4.000 1017.330 4.280 ;
        RECT 1018.170 4.000 1019.630 4.280 ;
        RECT 1020.470 4.000 1022.390 4.280 ;
        RECT 1023.230 4.000 1025.150 4.280 ;
        RECT 1025.990 4.000 1027.450 4.280 ;
        RECT 1028.290 4.000 1030.210 4.280 ;
        RECT 1031.050 4.000 1032.510 4.280 ;
        RECT 1033.350 4.000 1035.270 4.280 ;
        RECT 1036.110 4.000 1037.570 4.280 ;
        RECT 1038.410 4.000 1040.330 4.280 ;
        RECT 1041.170 4.000 1043.090 4.280 ;
        RECT 1043.930 4.000 1045.390 4.280 ;
        RECT 1046.230 4.000 1048.150 4.280 ;
        RECT 1048.990 4.000 1050.450 4.280 ;
        RECT 1051.290 4.000 1053.210 4.280 ;
        RECT 1054.050 4.000 1055.970 4.280 ;
        RECT 1056.810 4.000 1058.270 4.280 ;
        RECT 1059.110 4.000 1061.030 4.280 ;
        RECT 1061.870 4.000 1063.330 4.280 ;
        RECT 1064.170 4.000 1066.090 4.280 ;
        RECT 1066.930 4.000 1068.390 4.280 ;
        RECT 1069.230 4.000 1071.150 4.280 ;
        RECT 1071.990 4.000 1073.910 4.280 ;
        RECT 1074.750 4.000 1076.210 4.280 ;
        RECT 1077.050 4.000 1078.970 4.280 ;
        RECT 1079.810 4.000 1081.270 4.280 ;
        RECT 1082.110 4.000 1084.030 4.280 ;
        RECT 1084.870 4.000 1086.790 4.280 ;
        RECT 1087.630 4.000 1089.090 4.280 ;
        RECT 1089.930 4.000 1091.850 4.280 ;
        RECT 1092.690 4.000 1094.150 4.280 ;
        RECT 1094.990 4.000 1096.910 4.280 ;
        RECT 1097.750 4.000 1099.210 4.280 ;
        RECT 1100.050 4.000 1101.970 4.280 ;
        RECT 1102.810 4.000 1104.730 4.280 ;
        RECT 1105.570 4.000 1107.030 4.280 ;
        RECT 1107.870 4.000 1109.790 4.280 ;
        RECT 1110.630 4.000 1112.090 4.280 ;
        RECT 1112.930 4.000 1114.850 4.280 ;
        RECT 1115.690 4.000 1117.610 4.280 ;
        RECT 1118.450 4.000 1119.910 4.280 ;
        RECT 1120.750 4.000 1122.670 4.280 ;
        RECT 1123.510 4.000 1124.970 4.280 ;
        RECT 1125.810 4.000 1127.730 4.280 ;
        RECT 1128.570 4.000 1130.030 4.280 ;
        RECT 1130.870 4.000 1132.790 4.280 ;
        RECT 1133.630 4.000 1135.550 4.280 ;
        RECT 1136.390 4.000 1137.850 4.280 ;
        RECT 1138.690 4.000 1140.610 4.280 ;
        RECT 1141.450 4.000 1142.910 4.280 ;
        RECT 1143.750 4.000 1145.670 4.280 ;
        RECT 1146.510 4.000 1147.970 4.280 ;
        RECT 1148.810 4.000 1150.730 4.280 ;
        RECT 1151.570 4.000 1153.490 4.280 ;
        RECT 1154.330 4.000 1155.790 4.280 ;
        RECT 1156.630 4.000 1158.550 4.280 ;
        RECT 1159.390 4.000 1160.850 4.280 ;
        RECT 1161.690 4.000 1163.610 4.280 ;
        RECT 1164.450 4.000 1166.370 4.280 ;
        RECT 1167.210 4.000 1168.670 4.280 ;
        RECT 1169.510 4.000 1171.430 4.280 ;
        RECT 1172.270 4.000 1173.730 4.280 ;
        RECT 1174.570 4.000 1176.490 4.280 ;
        RECT 1177.330 4.000 1178.790 4.280 ;
        RECT 1179.630 4.000 1181.550 4.280 ;
        RECT 1182.390 4.000 1184.310 4.280 ;
        RECT 1185.150 4.000 1186.610 4.280 ;
        RECT 1187.450 4.000 1189.370 4.280 ;
        RECT 1190.210 4.000 1191.670 4.280 ;
        RECT 1192.510 4.000 1194.430 4.280 ;
        RECT 1195.270 4.000 1197.190 4.280 ;
        RECT 1198.030 4.000 1199.490 4.280 ;
        RECT 1200.330 4.000 1202.250 4.280 ;
        RECT 1203.090 4.000 1204.550 4.280 ;
        RECT 1205.390 4.000 1207.310 4.280 ;
        RECT 1208.150 4.000 1209.610 4.280 ;
        RECT 1210.450 4.000 1212.370 4.280 ;
        RECT 1213.210 4.000 1215.130 4.280 ;
        RECT 1215.970 4.000 1217.430 4.280 ;
        RECT 1218.270 4.000 1220.190 4.280 ;
        RECT 1221.030 4.000 1222.490 4.280 ;
        RECT 1223.330 4.000 1225.250 4.280 ;
        RECT 1226.090 4.000 1228.010 4.280 ;
        RECT 1228.850 4.000 1230.310 4.280 ;
        RECT 1231.150 4.000 1233.070 4.280 ;
        RECT 1233.910 4.000 1235.370 4.280 ;
        RECT 1236.210 4.000 1238.130 4.280 ;
        RECT 1238.970 4.000 1240.430 4.280 ;
        RECT 1241.270 4.000 1243.190 4.280 ;
        RECT 1244.030 4.000 1245.950 4.280 ;
        RECT 1246.790 4.000 1248.250 4.280 ;
        RECT 1249.090 4.000 1251.010 4.280 ;
        RECT 1251.850 4.000 1253.310 4.280 ;
      LAYER met3 ;
        RECT 4.000 1254.960 1254.125 1256.805 ;
        RECT 4.000 1254.280 1253.725 1254.960 ;
        RECT 4.400 1253.560 1253.725 1254.280 ;
        RECT 4.400 1252.880 1254.125 1253.560 ;
        RECT 4.000 1227.080 1254.125 1252.880 ;
        RECT 4.000 1225.680 1253.725 1227.080 ;
        RECT 4.000 1224.360 1254.125 1225.680 ;
        RECT 4.400 1222.960 1254.125 1224.360 ;
        RECT 4.000 1198.520 1254.125 1222.960 ;
        RECT 4.000 1197.120 1253.725 1198.520 ;
        RECT 4.000 1193.760 1254.125 1197.120 ;
        RECT 4.400 1192.360 1254.125 1193.760 ;
        RECT 4.000 1170.640 1254.125 1192.360 ;
        RECT 4.000 1169.240 1253.725 1170.640 ;
        RECT 4.000 1163.840 1254.125 1169.240 ;
        RECT 4.400 1162.440 1254.125 1163.840 ;
        RECT 4.000 1142.080 1254.125 1162.440 ;
        RECT 4.000 1140.680 1253.725 1142.080 ;
        RECT 4.000 1133.240 1254.125 1140.680 ;
        RECT 4.400 1131.840 1254.125 1133.240 ;
        RECT 4.000 1114.200 1254.125 1131.840 ;
        RECT 4.000 1112.800 1253.725 1114.200 ;
        RECT 4.000 1103.320 1254.125 1112.800 ;
        RECT 4.400 1101.920 1254.125 1103.320 ;
        RECT 4.000 1085.640 1254.125 1101.920 ;
        RECT 4.000 1084.240 1253.725 1085.640 ;
        RECT 4.000 1073.400 1254.125 1084.240 ;
        RECT 4.400 1072.000 1254.125 1073.400 ;
        RECT 4.000 1057.760 1254.125 1072.000 ;
        RECT 4.000 1056.360 1253.725 1057.760 ;
        RECT 4.000 1042.800 1254.125 1056.360 ;
        RECT 4.400 1041.400 1254.125 1042.800 ;
        RECT 4.000 1029.200 1254.125 1041.400 ;
        RECT 4.000 1027.800 1253.725 1029.200 ;
        RECT 4.000 1012.880 1254.125 1027.800 ;
        RECT 4.400 1011.480 1254.125 1012.880 ;
        RECT 4.000 1001.320 1254.125 1011.480 ;
        RECT 4.000 999.920 1253.725 1001.320 ;
        RECT 4.000 982.280 1254.125 999.920 ;
        RECT 4.400 980.880 1254.125 982.280 ;
        RECT 4.000 972.760 1254.125 980.880 ;
        RECT 4.000 971.360 1253.725 972.760 ;
        RECT 4.000 952.360 1254.125 971.360 ;
        RECT 4.400 950.960 1254.125 952.360 ;
        RECT 4.000 944.880 1254.125 950.960 ;
        RECT 4.000 943.480 1253.725 944.880 ;
        RECT 4.000 921.760 1254.125 943.480 ;
        RECT 4.400 920.360 1254.125 921.760 ;
        RECT 4.000 916.320 1254.125 920.360 ;
        RECT 4.000 914.920 1253.725 916.320 ;
        RECT 4.000 891.840 1254.125 914.920 ;
        RECT 4.400 890.440 1254.125 891.840 ;
        RECT 4.000 888.440 1254.125 890.440 ;
        RECT 4.000 887.040 1253.725 888.440 ;
        RECT 4.000 861.920 1254.125 887.040 ;
        RECT 4.400 860.560 1254.125 861.920 ;
        RECT 4.400 860.520 1253.725 860.560 ;
        RECT 4.000 859.160 1253.725 860.520 ;
        RECT 4.000 832.000 1254.125 859.160 ;
        RECT 4.000 831.320 1253.725 832.000 ;
        RECT 4.400 830.600 1253.725 831.320 ;
        RECT 4.400 829.920 1254.125 830.600 ;
        RECT 4.000 804.120 1254.125 829.920 ;
        RECT 4.000 802.720 1253.725 804.120 ;
        RECT 4.000 801.400 1254.125 802.720 ;
        RECT 4.400 800.000 1254.125 801.400 ;
        RECT 4.000 775.560 1254.125 800.000 ;
        RECT 4.000 774.160 1253.725 775.560 ;
        RECT 4.000 770.800 1254.125 774.160 ;
        RECT 4.400 769.400 1254.125 770.800 ;
        RECT 4.000 747.680 1254.125 769.400 ;
        RECT 4.000 746.280 1253.725 747.680 ;
        RECT 4.000 740.880 1254.125 746.280 ;
        RECT 4.400 739.480 1254.125 740.880 ;
        RECT 4.000 719.120 1254.125 739.480 ;
        RECT 4.000 717.720 1253.725 719.120 ;
        RECT 4.000 710.280 1254.125 717.720 ;
        RECT 4.400 708.880 1254.125 710.280 ;
        RECT 4.000 691.240 1254.125 708.880 ;
        RECT 4.000 689.840 1253.725 691.240 ;
        RECT 4.000 680.360 1254.125 689.840 ;
        RECT 4.400 678.960 1254.125 680.360 ;
        RECT 4.000 662.680 1254.125 678.960 ;
        RECT 4.000 661.280 1253.725 662.680 ;
        RECT 4.000 650.440 1254.125 661.280 ;
        RECT 4.400 649.040 1254.125 650.440 ;
        RECT 4.000 634.800 1254.125 649.040 ;
        RECT 4.000 633.400 1253.725 634.800 ;
        RECT 4.000 619.840 1254.125 633.400 ;
        RECT 4.400 618.440 1254.125 619.840 ;
        RECT 4.000 606.240 1254.125 618.440 ;
        RECT 4.000 604.840 1253.725 606.240 ;
        RECT 4.000 589.920 1254.125 604.840 ;
        RECT 4.400 588.520 1254.125 589.920 ;
        RECT 4.000 578.360 1254.125 588.520 ;
        RECT 4.000 576.960 1253.725 578.360 ;
        RECT 4.000 559.320 1254.125 576.960 ;
        RECT 4.400 557.920 1254.125 559.320 ;
        RECT 4.000 549.800 1254.125 557.920 ;
        RECT 4.000 548.400 1253.725 549.800 ;
        RECT 4.000 529.400 1254.125 548.400 ;
        RECT 4.400 528.000 1254.125 529.400 ;
        RECT 4.000 521.920 1254.125 528.000 ;
        RECT 4.000 520.520 1253.725 521.920 ;
        RECT 4.000 498.800 1254.125 520.520 ;
        RECT 4.400 497.400 1254.125 498.800 ;
        RECT 4.000 493.360 1254.125 497.400 ;
        RECT 4.000 491.960 1253.725 493.360 ;
        RECT 4.000 468.880 1254.125 491.960 ;
        RECT 4.400 467.480 1254.125 468.880 ;
        RECT 4.000 465.480 1254.125 467.480 ;
        RECT 4.000 464.080 1253.725 465.480 ;
        RECT 4.000 438.960 1254.125 464.080 ;
        RECT 4.400 437.600 1254.125 438.960 ;
        RECT 4.400 437.560 1253.725 437.600 ;
        RECT 4.000 436.200 1253.725 437.560 ;
        RECT 4.000 409.040 1254.125 436.200 ;
        RECT 4.000 408.360 1253.725 409.040 ;
        RECT 4.400 407.640 1253.725 408.360 ;
        RECT 4.400 406.960 1254.125 407.640 ;
        RECT 4.000 381.160 1254.125 406.960 ;
        RECT 4.000 379.760 1253.725 381.160 ;
        RECT 4.000 378.440 1254.125 379.760 ;
        RECT 4.400 377.040 1254.125 378.440 ;
        RECT 4.000 352.600 1254.125 377.040 ;
        RECT 4.000 351.200 1253.725 352.600 ;
        RECT 4.000 347.840 1254.125 351.200 ;
        RECT 4.400 346.440 1254.125 347.840 ;
        RECT 4.000 324.720 1254.125 346.440 ;
        RECT 4.000 323.320 1253.725 324.720 ;
        RECT 4.000 317.920 1254.125 323.320 ;
        RECT 4.400 316.520 1254.125 317.920 ;
        RECT 4.000 296.160 1254.125 316.520 ;
        RECT 4.000 294.760 1253.725 296.160 ;
        RECT 4.000 287.320 1254.125 294.760 ;
        RECT 4.400 285.920 1254.125 287.320 ;
        RECT 4.000 268.280 1254.125 285.920 ;
        RECT 4.000 266.880 1253.725 268.280 ;
        RECT 4.000 257.400 1254.125 266.880 ;
        RECT 4.400 256.000 1254.125 257.400 ;
        RECT 4.000 239.720 1254.125 256.000 ;
        RECT 4.000 238.320 1253.725 239.720 ;
        RECT 4.000 227.480 1254.125 238.320 ;
        RECT 4.400 226.080 1254.125 227.480 ;
        RECT 4.000 211.840 1254.125 226.080 ;
        RECT 4.000 210.440 1253.725 211.840 ;
        RECT 4.000 196.880 1254.125 210.440 ;
        RECT 4.400 195.480 1254.125 196.880 ;
        RECT 4.000 183.280 1254.125 195.480 ;
        RECT 4.000 181.880 1253.725 183.280 ;
        RECT 4.000 166.960 1254.125 181.880 ;
        RECT 4.400 165.560 1254.125 166.960 ;
        RECT 4.000 155.400 1254.125 165.560 ;
        RECT 4.000 154.000 1253.725 155.400 ;
        RECT 4.000 136.360 1254.125 154.000 ;
        RECT 4.400 134.960 1254.125 136.360 ;
        RECT 4.000 126.840 1254.125 134.960 ;
        RECT 4.000 125.440 1253.725 126.840 ;
        RECT 4.000 106.440 1254.125 125.440 ;
        RECT 4.400 105.040 1254.125 106.440 ;
        RECT 4.000 98.960 1254.125 105.040 ;
        RECT 4.000 97.560 1253.725 98.960 ;
        RECT 4.000 75.840 1254.125 97.560 ;
        RECT 4.400 74.440 1254.125 75.840 ;
        RECT 4.000 70.400 1254.125 74.440 ;
        RECT 4.000 69.000 1253.725 70.400 ;
        RECT 4.000 45.920 1254.125 69.000 ;
        RECT 4.400 44.520 1254.125 45.920 ;
        RECT 4.000 42.520 1254.125 44.520 ;
        RECT 4.000 41.120 1253.725 42.520 ;
        RECT 4.000 16.000 1254.125 41.120 ;
        RECT 4.400 14.640 1254.125 16.000 ;
        RECT 4.400 14.600 1253.725 14.640 ;
        RECT 4.000 13.240 1253.725 14.600 ;
        RECT 4.000 10.715 1254.125 13.240 ;
      LAYER met4 ;
        RECT 109.775 61.375 174.240 1136.105 ;
        RECT 176.640 61.375 177.540 1136.105 ;
        RECT 179.940 61.375 180.840 1136.105 ;
        RECT 183.240 61.375 184.140 1136.105 ;
        RECT 186.540 61.375 251.040 1136.105 ;
        RECT 253.440 61.375 254.340 1136.105 ;
        RECT 256.740 61.375 257.640 1136.105 ;
        RECT 260.040 61.375 260.940 1136.105 ;
        RECT 263.340 61.375 327.840 1136.105 ;
        RECT 330.240 61.375 331.140 1136.105 ;
        RECT 333.540 61.375 334.440 1136.105 ;
        RECT 336.840 61.375 337.740 1136.105 ;
        RECT 340.140 61.375 404.640 1136.105 ;
        RECT 407.040 61.375 407.940 1136.105 ;
        RECT 410.340 61.375 411.240 1136.105 ;
        RECT 413.640 61.375 414.540 1136.105 ;
        RECT 416.940 61.375 481.440 1136.105 ;
        RECT 483.840 61.375 484.740 1136.105 ;
        RECT 487.140 61.375 488.040 1136.105 ;
        RECT 490.440 61.375 491.340 1136.105 ;
        RECT 493.740 61.375 558.240 1136.105 ;
        RECT 560.640 61.375 561.540 1136.105 ;
        RECT 563.940 61.375 564.840 1136.105 ;
        RECT 567.240 61.375 568.140 1136.105 ;
        RECT 570.540 61.375 635.040 1136.105 ;
        RECT 637.440 61.375 638.340 1136.105 ;
        RECT 640.740 61.375 641.640 1136.105 ;
        RECT 644.040 61.375 644.940 1136.105 ;
        RECT 647.340 61.375 711.840 1136.105 ;
        RECT 714.240 61.375 715.140 1136.105 ;
        RECT 717.540 61.375 718.440 1136.105 ;
        RECT 720.840 61.375 721.740 1136.105 ;
        RECT 724.140 61.375 788.640 1136.105 ;
        RECT 791.040 61.375 791.940 1136.105 ;
        RECT 794.340 61.375 795.240 1136.105 ;
        RECT 797.640 61.375 798.540 1136.105 ;
        RECT 800.940 61.375 865.440 1136.105 ;
        RECT 867.840 61.375 868.740 1136.105 ;
        RECT 871.140 61.375 872.040 1136.105 ;
        RECT 874.440 61.375 875.340 1136.105 ;
        RECT 877.740 61.375 942.240 1136.105 ;
        RECT 944.640 61.375 945.540 1136.105 ;
        RECT 947.940 61.375 948.840 1136.105 ;
        RECT 951.240 61.375 952.140 1136.105 ;
        RECT 954.540 61.375 1019.040 1136.105 ;
        RECT 1021.440 61.375 1022.340 1136.105 ;
        RECT 1024.740 61.375 1025.640 1136.105 ;
        RECT 1028.040 61.375 1028.940 1136.105 ;
        RECT 1031.340 61.375 1095.840 1136.105 ;
        RECT 1098.240 61.375 1099.140 1136.105 ;
        RECT 1101.540 61.375 1102.440 1136.105 ;
        RECT 1104.840 61.375 1105.740 1136.105 ;
        RECT 1108.140 61.375 1117.505 1136.105 ;
  END
END accelerator_top
END LIBRARY

